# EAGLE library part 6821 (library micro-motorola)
MICROCONTROLLER/MEMORY DEVICE

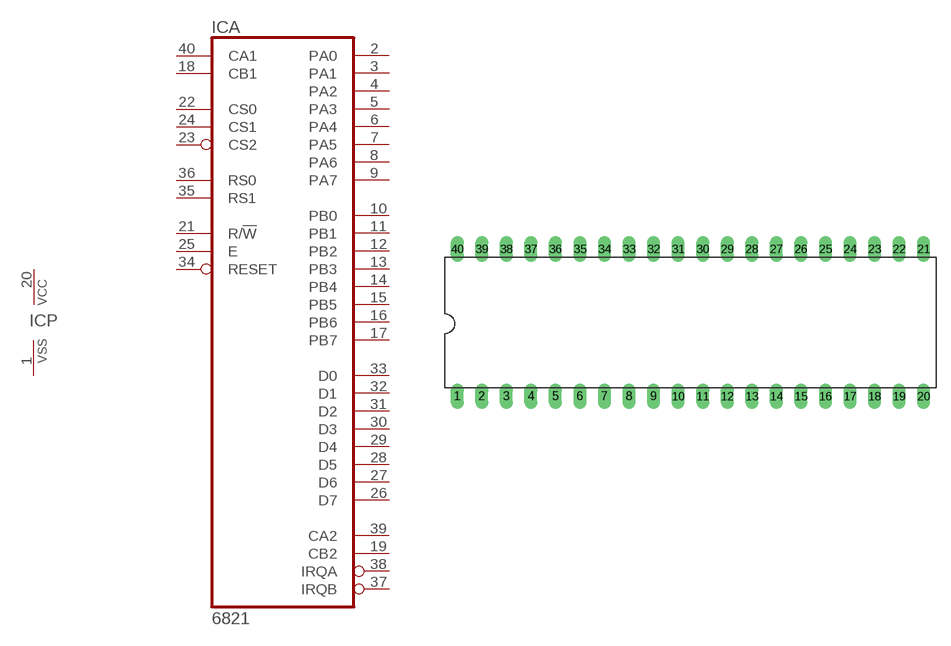
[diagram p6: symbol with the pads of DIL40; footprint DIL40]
Designator prefix IC; gates A=6821 P=PWRVSS

## 6821 (MF: NTE ELECTRONICS; MPN: NTE6821; OC_FARNELL: 1652403; OC_NEWARK: 29C4772)  [DIL40]
1  P:VSS  pwr
2  A:PA0
3  A:PA1
4  A:PA2
5  A:PA3
6  A:PA4
7  A:PA5
8  A:PA6
9  A:PA7
10  A:PB0
11  A:PB1
12  A:PB2
13  A:PB3
14  A:PB4
15  A:PB5
16  A:PB6
17  A:PB7
18  A:CB1  in
19  A:CB2
20  P:VCC  pwr
21  A:R/!W  in
22  A:CS0  in
23  A:CS2  in
24  A:CS1  in
25  A:E  in
26  A:D7
27  A:D6
28  A:D5
29  A:D4
30  A:D3
31  A:D2
32  A:D1
33  A:D0
34  A:RESET  in
35  A:RS1  in
36  A:RS0  in
37  A:IRQB  oc
38  A:IRQA  oc
39  A:CA2
40  A:CA1  in

## Footprint DIL40 (pad centres in mm)
Dual In Line Package
drill 0.813 long: 1 -24.13,-7.62; 2 -21.59,-7.62; 3 -19.05,-7.62; 4 -16.51,-7.62; 5 -13.97,-7.62; 6 -11.43,-7.62; 7 -8.89,-7.62; 8 -6.35,-7.62; 9 -3.81,-7.62; 10 -1.27,-7.62; 11 1.27,-7.62; 12 3.81,-7.62; 13 6.35,-7.62; 14 8.89,-7.62; 15 11.43,-7.62; 16 13.97,-7.62; 17 16.51,-7.62; 18 19.05,-7.62; 19 21.59,-7.62; 20 24.13,-7.62; 21 24.13,7.62; 22 21.59,7.62; 23 19.05,7.62; 24 16.51,7.62; 25 13.97,7.62; 26 11.43,7.62; 27 8.89,7.62; 28 6.35,7.62; 29 3.81,7.62; 30 1.27,7.62; 31 -1.27,7.62; 32 -3.81,7.62; 33 -6.35,7.62; 34 -8.89,7.62; 35 -11.43,7.62; 36 -13.97,7.62; 37 -16.51,7.62; 38 -19.05,7.62; 39 -21.59,7.62; 40 -24.13,7.62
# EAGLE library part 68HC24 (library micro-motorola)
MICROCONTROLLER/MEMORY DEVICE

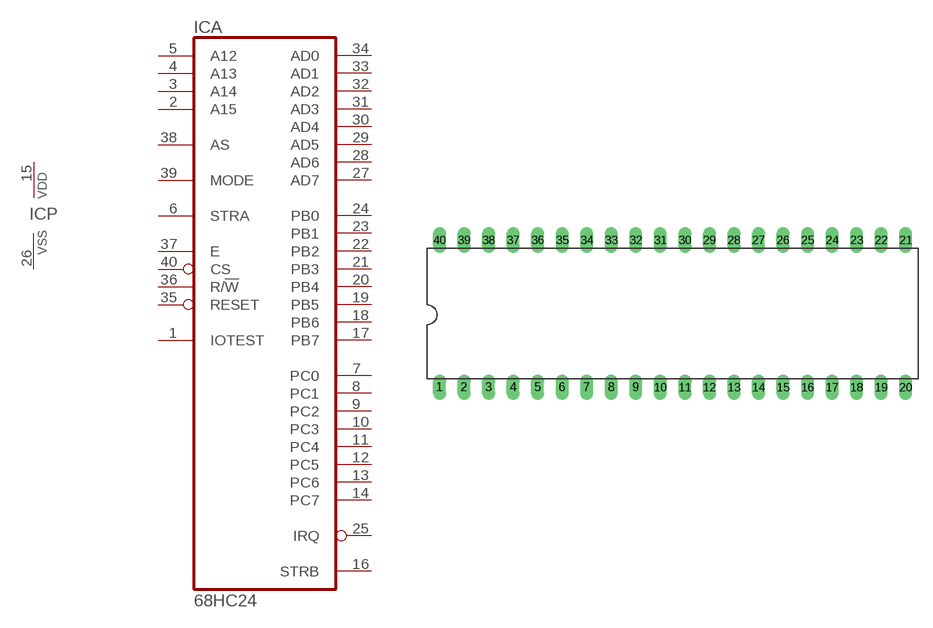
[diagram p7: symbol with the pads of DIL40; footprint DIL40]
Designator prefix IC; gates A=68HC24 P=VSSVDD

## 68HC24 (OC_FARNELL: unknown; OC_NEWARK: unknown)  [DIL40]
1  A:IOTEST  in
2  A:A15  in
3  A:A14  in
4  A:A13  in
5  A:A12  in
6  A:STRA  in
7  A:PC0
8  A:PC1
9  A:PC2
10  A:PC3
11  A:PC4
12  A:PC5
13  A:PC6
14  A:PC7
15  P:VDD  pwr
16  A:STRB  out
17  A:PB7  out
18  A:PB6  out
19  A:PB5  out
20  A:PB4  out
21  A:PB3  out
22  A:PB2  out
23  A:PB1  out
24  A:PB0  out
25  A:IRQ  out
26  P:VSS  pwr
27  A:AD7
28  A:AD6
29  A:AD5
30  A:AD4
31  A:AD3
32  A:AD2
33  A:AD1
34  A:AD0
35  A:RESET  in
36  A:R/!W  in
37  A:E  in
38  A:AS  in
39  A:MODE  in
40  A:CS  in

## Footprint DIL40 (pad centres in mm)
Dual In Line Package
drill 0.813 long: 1 -24.13,-7.62; 2 -21.59,-7.62; 3 -19.05,-7.62; 4 -16.51,-7.62; 5 -13.97,-7.62; 6 -11.43,-7.62; 7 -8.89,-7.62; 8 -6.35,-7.62; 9 -3.81,-7.62; 10 -1.27,-7.62; 11 1.27,-7.62; 12 3.81,-7.62; 13 6.35,-7.62; 14 8.89,-7.62; 15 11.43,-7.62; 16 13.97,-7.62; 17 16.51,-7.62; 18 19.05,-7.62; 19 21.59,-7.62; 20 24.13,-7.62; 21 24.13,7.62; 22 21.59,7.62; 23 19.05,7.62; 24 16.51,7.62; 25 13.97,7.62; 26 11.43,7.62; 27 8.89,7.62; 28 6.35,7.62; 29 3.81,7.62; 30 1.27,7.62; 31 -1.27,7.62; 32 -3.81,7.62; 33 -6.35,7.62; 34 -8.89,7.62; 35 -11.43,7.62; 36 -13.97,7.62; 37 -16.51,7.62; 38 -19.05,7.62; 39 -21.59,7.62; 40 -24.13,7.62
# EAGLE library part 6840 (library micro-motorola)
MICROCONTROLLER/MEMORY DEVICE

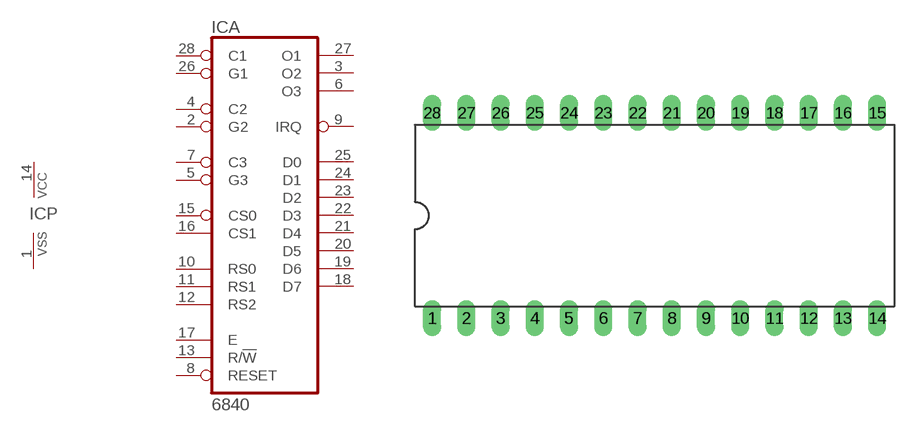
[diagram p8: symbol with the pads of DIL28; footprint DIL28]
Designator prefix IC; gates A=6840 P=PWRVSS

## 6840 (OC_FARNELL: unknown; OC_NEWARK: unknown)  [DIL28]
1  P:VSS  pwr
2  A:G2  in
3  A:O2  out
4  A:C2  in
5  A:G3  in
6  A:O3  out
7  A:C3  in
8  A:RESET  in
9  A:IRQ  oc
10  A:RS0  in
11  A:RS1  in
12  A:RS2  in
13  A:R/!W  in
14  P:VCC  pwr
15  A:CS0  in
16  A:CS1  in
17  A:E  in
18  A:D7
19  A:D6
20  A:D5
21  A:D4
22  A:D3
23  A:D2
24  A:D1
25  A:D0
26  A:G1  in
27  A:O1  out
28  A:C1  in

## Footprint DIL28 (pad centres in mm)
Dual In Line Package
drill 0.813 long: 1 -16.51,-7.62; 2 -13.97,-7.62; 3 -11.43,-7.62; 4 -8.89,-7.62; 5 -6.35,-7.62; 6 -3.81,-7.62; 7 -1.27,-7.62; 8 1.27,-7.62; 9 3.81,-7.62; 10 6.35,-7.62; 11 8.89,-7.62; 12 11.43,-7.62; 13 13.97,-7.62; 14 16.51,-7.62; 15 16.51,7.62; 16 13.97,7.62; 17 11.43,7.62; 18 8.89,7.62; 19 6.35,7.62; 20 3.81,7.62; 21 1.27,7.62; 22 -1.27,7.62; 23 -3.81,7.62; 24 -6.35,7.62; 25 -8.89,7.62; 26 -11.43,7.62; 27 -13.97,7.62; 28 -16.51,7.62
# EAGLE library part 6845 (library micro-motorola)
MICROCONTROLLER/MEMORY DEVICE

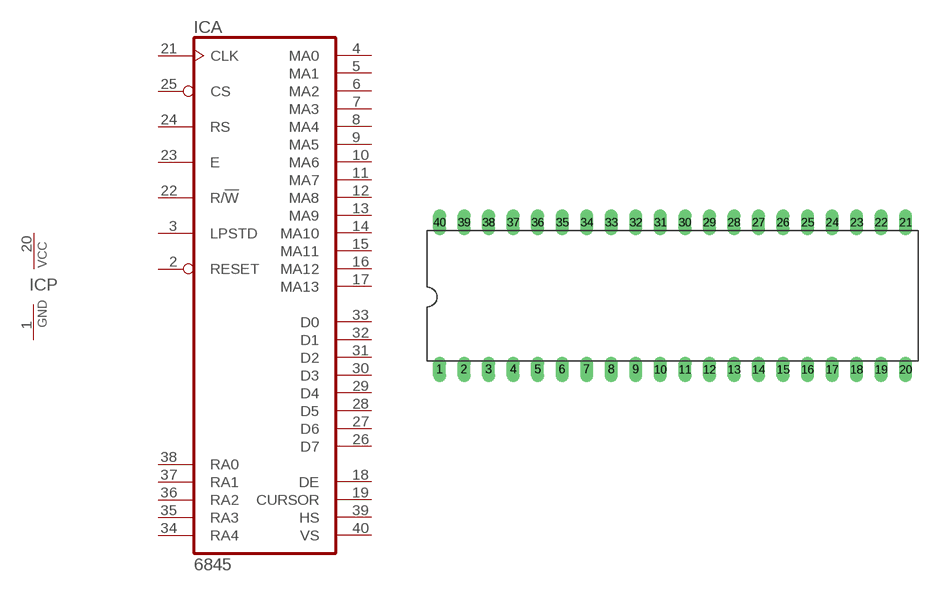
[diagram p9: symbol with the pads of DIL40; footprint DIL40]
Designator prefix IC; gates A=6845 P=PWRN

## 6845 (OC_FARNELL: unknown; OC_NEWARK: unknown)  [DIL40]
1  P:GND  pwr
2  A:RESET  in
3  A:LPSTD  in
4  A:MA0  out
5  A:MA1  out
6  A:MA2  out
7  A:MA3  out
8  A:MA4  out
9  A:MA5  out
10  A:MA6  out
11  A:MA7  out
12  A:MA8  out
13  A:MA9  out
14  A:MA10  out
15  A:MA11  out
16  A:MA12  out
17  A:MA13  out
18  A:DE  out
19  A:CURSOR  out
20  P:VCC  pwr
21  A:CLK  in
22  A:R/!W  in
23  A:E  in
24  A:RS  in
25  A:CS  in
26  A:D7  out
27  A:D6  out
28  A:D5  out
29  A:D4  out
30  A:D3  out
31  A:D2  out
32  A:D1  out
33  A:D0  out
34  A:RA4  out
35  A:RA3  out
36  A:RA2  out
37  A:RA1  out
38  A:RA0  out
39  A:HS  out
40  A:VS  out

## Footprint DIL40 (pad centres in mm)
Dual In Line Package
drill 0.813 long: 1 -24.13,-7.62; 2 -21.59,-7.62; 3 -19.05,-7.62; 4 -16.51,-7.62; 5 -13.97,-7.62; 6 -11.43,-7.62; 7 -8.89,-7.62; 8 -6.35,-7.62; 9 -3.81,-7.62; 10 -1.27,-7.62; 11 1.27,-7.62; 12 3.81,-7.62; 13 6.35,-7.62; 14 8.89,-7.62; 15 11.43,-7.62; 16 13.97,-7.62; 17 16.51,-7.62; 18 19.05,-7.62; 19 21.59,-7.62; 20 24.13,-7.62; 21 24.13,7.62; 22 21.59,7.62; 23 19.05,7.62; 24 16.51,7.62; 25 13.97,7.62; 26 11.43,7.62; 27 8.89,7.62; 28 6.35,7.62; 29 3.81,7.62; 30 1.27,7.62; 31 -1.27,7.62; 32 -3.81,7.62; 33 -6.35,7.62; 34 -8.89,7.62; 35 -11.43,7.62; 36 -13.97,7.62; 37 -16.51,7.62; 38 -19.05,7.62; 39 -21.59,7.62; 40 -24.13,7.62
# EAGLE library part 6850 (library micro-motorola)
MICROCONTROLLER/MEMORY DEVICE

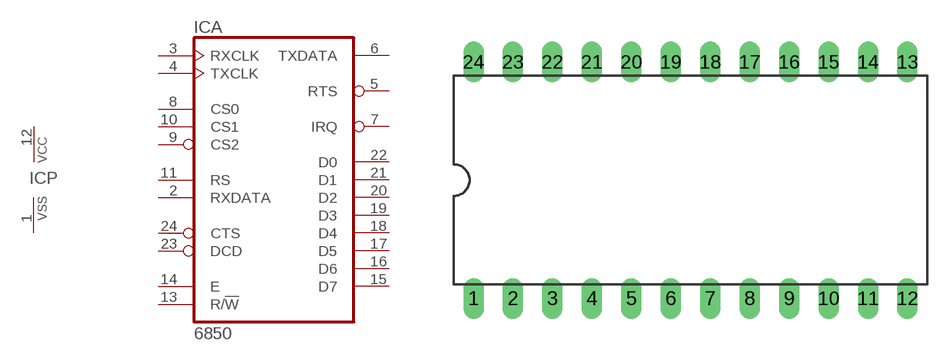
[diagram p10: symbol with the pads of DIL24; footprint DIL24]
Designator prefix IC; gates A=6850 P=PWRVSS

## 6850 (MF: NTE ELECTRONICS; MPN: NTE6850; OC_FARNELL: 4899775; OC_NEWARK: 31C2457)  [DIL24]
1  P:VSS  pwr
2  A:RXDATA  in
3  A:RXCLK  in
4  A:TXCLK  in
5  A:RTS  out
6  A:TXDATA  out
7  A:IRQ  out
8  A:CS0  in
9  A:CS2  in
10  A:CS1  in
11  A:RS  in
12  P:VCC  pwr
13  A:R/!W  in
14  A:E  in
15  A:D7
16  A:D6
17  A:D5
18  A:D4
19  A:D3
20  A:D2
21  A:D1
22  A:D0
23  A:DCD  in
24  A:CTS  in

## Footprint DIL24 (pad centres in mm)
Dual In Line Package
drill 0.813 long: 1 -13.97,-7.62; 2 -11.43,-7.62; 3 -8.89,-7.62; 4 -6.35,-7.62; 5 -3.81,-7.62; 6 -1.27,-7.62; 7 1.27,-7.62; 8 3.81,-7.62; 9 6.35,-7.62; 10 8.89,-7.62; 11 11.43,-7.62; 12 13.97,-7.62; 13 13.97,7.62; 14 11.43,7.62; 15 8.89,7.62; 16 6.35,7.62; 17 3.81,7.62; 18 1.27,7.62; 19 -1.27,7.62; 20 -3.81,7.62; 21 -6.35,7.62; 22 -8.89,7.62; 23 -11.43,7.62; 24 -13.97,7.62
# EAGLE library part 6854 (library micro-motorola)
MICROCONTROLLER/MEMORY DEVICE

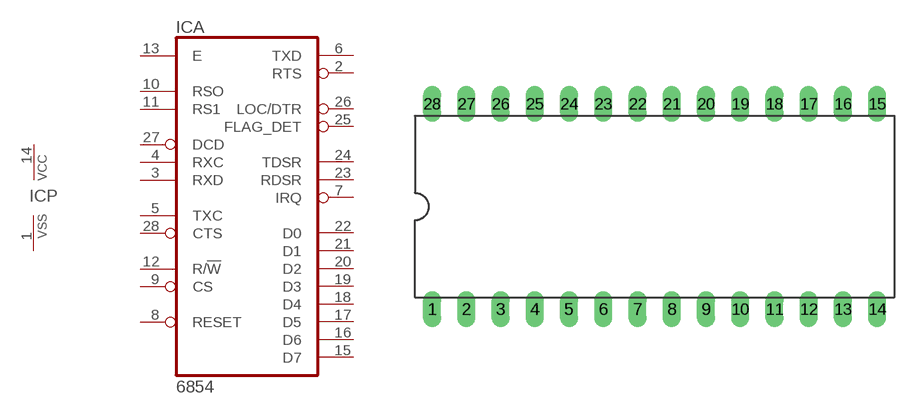
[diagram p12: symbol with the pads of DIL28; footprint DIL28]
Designator prefix IC; gates A=6854 P=PWRVSS

## 6854 (OC_FARNELL: unknown; OC_NEWARK: unknown)  [DIL28]
1  P:VSS  pwr
2  A:RTS  out
3  A:RXD  in
4  A:RXC  in
5  A:TXC  in
6  A:TXD  out
7  A:IRQ  out
8  A:RESET  in
9  A:CS  in
10  A:RSO  in
11  A:RS1  in
12  A:R/!W  in
13  A:E  in
14  P:VCC  pwr
15  A:D7
16  A:D6
17  A:D5
18  A:D4
19  A:D3
20  A:D2
21  A:D1
22  A:D0
23  A:RDSR  out
24  A:TDSR  out
25  A:FLAG_DET  out
26  A:LOC/DTR  out
27  A:DCD  in
28  A:CTS  in

## Footprint DIL28 (pad centres in mm)
Dual In Line Package
drill 0.813 long: 1 -16.51,-7.62; 2 -13.97,-7.62; 3 -11.43,-7.62; 4 -8.89,-7.62; 5 -6.35,-7.62; 6 -3.81,-7.62; 7 -1.27,-7.62; 8 1.27,-7.62; 9 3.81,-7.62; 10 6.35,-7.62; 11 8.89,-7.62; 12 11.43,-7.62; 13 13.97,-7.62; 14 16.51,-7.62; 15 16.51,7.62; 16 13.97,7.62; 17 11.43,7.62; 18 8.89,7.62; 19 6.35,7.62; 20 3.81,7.62; 21 1.27,7.62; 22 -1.27,7.62; 23 -3.81,7.62; 24 -6.35,7.62; 25 -8.89,7.62; 26 -11.43,7.62; 27 -13.97,7.62; 28 -16.51,7.62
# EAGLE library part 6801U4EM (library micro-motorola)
MICROCONTROLLER/MEMORY DEVICE

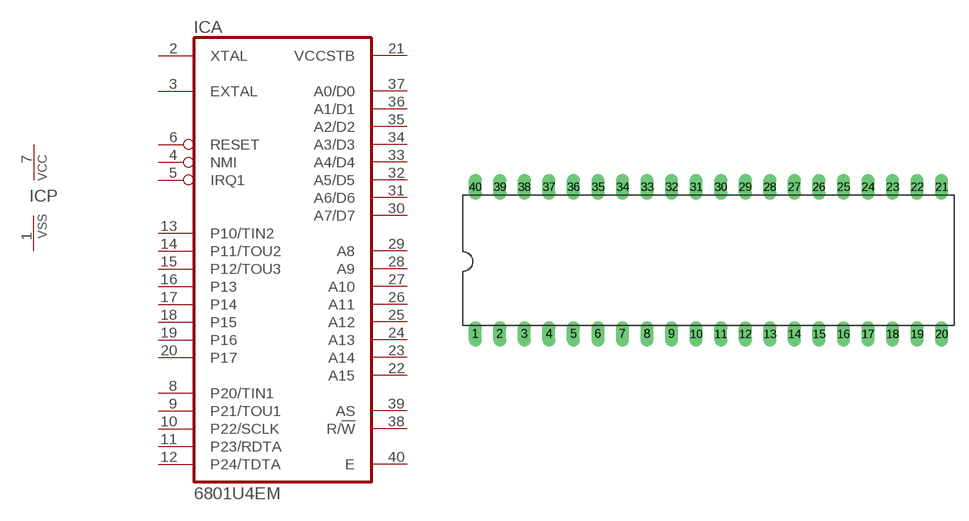
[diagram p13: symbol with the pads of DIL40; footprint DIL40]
Designator prefix IC; gates A=6801U4EM P=PWRVSS

## 6801U4EM (OC_FARNELL: unknown; OC_NEWARK: unknown)  [DIL40]
1  P:VSS  pwr
2  A:XTAL  in
3  A:EXTAL  in
4  A:NMI  in
5  A:IRQ1  in
6  A:RESET  in
7  P:VCC  pwr
8  A:P20/TIN1
9  A:P21/TOU1
10  A:P22/SCLK
11  A:P23/RDTA
12  A:P24/TDTA
13  A:P10/TIN2
14  A:P11/TOU2
15  A:P12/TOU3
16  A:P13
17  A:P14
18  A:P15
19  A:P16
20  A:P17
21  A:VCCSTB  in
22  A:A15
23  A:A14
24  A:A13
25  A:A12
26  A:A11
27  A:A10
28  A:A9
29  A:A8
30  A:A7/D7
31  A:A6/D6
32  A:A5/D5
33  A:A4/D4
34  A:A3/D3
35  A:A2/D2
36  A:A1/D1
37  A:A0/D0
38  A:R/!W  out
39  A:AS
40  A:E  out

## Footprint DIL40 (pad centres in mm)
Dual In Line Package
drill 0.813 long: 1 -24.13,-7.62; 2 -21.59,-7.62; 3 -19.05,-7.62; 4 -16.51,-7.62; 5 -13.97,-7.62; 6 -11.43,-7.62; 7 -8.89,-7.62; 8 -6.35,-7.62; 9 -3.81,-7.62; 10 -1.27,-7.62; 11 1.27,-7.62; 12 3.81,-7.62; 13 6.35,-7.62; 14 8.89,-7.62; 15 11.43,-7.62; 16 13.97,-7.62; 17 16.51,-7.62; 18 19.05,-7.62; 19 21.59,-7.62; 20 24.13,-7.62; 21 24.13,7.62; 22 21.59,7.62; 23 19.05,7.62; 24 16.51,7.62; 25 13.97,7.62; 26 11.43,7.62; 27 8.89,7.62; 28 6.35,7.62; 29 3.81,7.62; 30 1.27,7.62; 31 -1.27,7.62; 32 -3.81,7.62; 33 -6.35,7.62; 34 -8.89,7.62; 35 -11.43,7.62; 36 -13.97,7.62; 37 -16.51,7.62; 38 -19.05,7.62; 39 -21.59,7.62; 40 -24.13,7.62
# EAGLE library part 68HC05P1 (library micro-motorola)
MICROCONTROLLER/MEMORY DEVICE

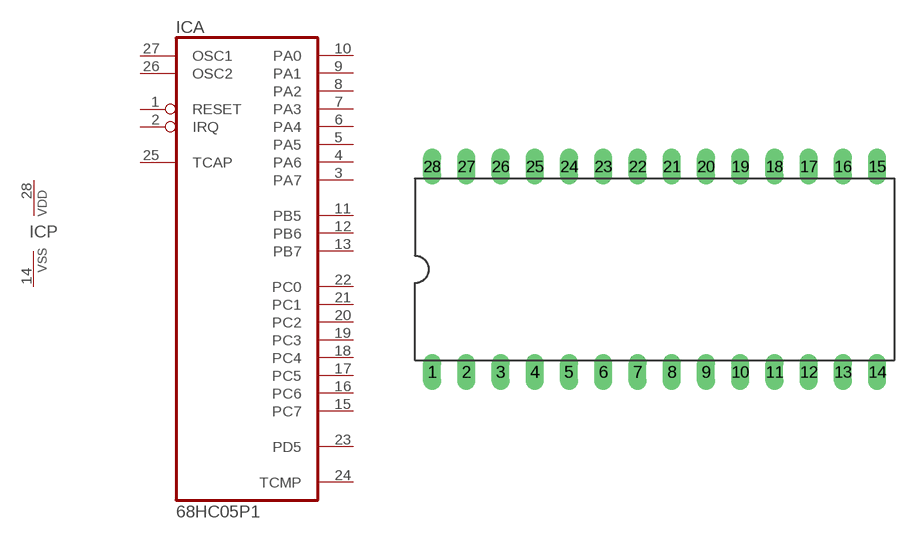
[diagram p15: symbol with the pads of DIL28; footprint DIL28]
Designator prefix IC; gates A=68HC05P1 P=VSSVDD

## 68HC05P1 (OC_FARNELL: unknown; OC_NEWARK: unknown)  [DIL28]
1  A:RESET  in
2  A:IRQ  in
3  A:PA7
4  A:PA6
5  A:PA5
6  A:PA4
7  A:PA3
8  A:PA2
9  A:PA1
10  A:PA0
11  A:PB5
12  A:PB6
13  A:PB7
14  P:VSS  pwr
15  A:PC7
16  A:PC6
17  A:PC5
18  A:PC4
19  A:PC3
20  A:PC2
21  A:PC1
22  A:PC0
23  A:PD5
24  A:TCMP  out
25  A:TCAP  in
26  A:OSC2  pas
27  A:OSC1  in
28  P:VDD  pwr

## Footprint DIL28 (pad centres in mm)
Dual In Line Package
drill 0.813 long: 1 -16.51,-7.62; 2 -13.97,-7.62; 3 -11.43,-7.62; 4 -8.89,-7.62; 5 -6.35,-7.62; 6 -3.81,-7.62; 7 -1.27,-7.62; 8 1.27,-7.62; 9 3.81,-7.62; 10 6.35,-7.62; 11 8.89,-7.62; 12 11.43,-7.62; 13 13.97,-7.62; 14 16.51,-7.62; 15 16.51,7.62; 16 13.97,7.62; 17 11.43,7.62; 18 8.89,7.62; 19 6.35,7.62; 20 3.81,7.62; 21 1.27,7.62; 22 -1.27,7.62; 23 -3.81,7.62; 24 -6.35,7.62; 25 -8.89,7.62; 26 -11.43,7.62; 27 -13.97,7.62; 28 -16.51,7.62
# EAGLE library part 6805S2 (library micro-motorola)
MICROCONTROLLER/MEMORY DEVICE

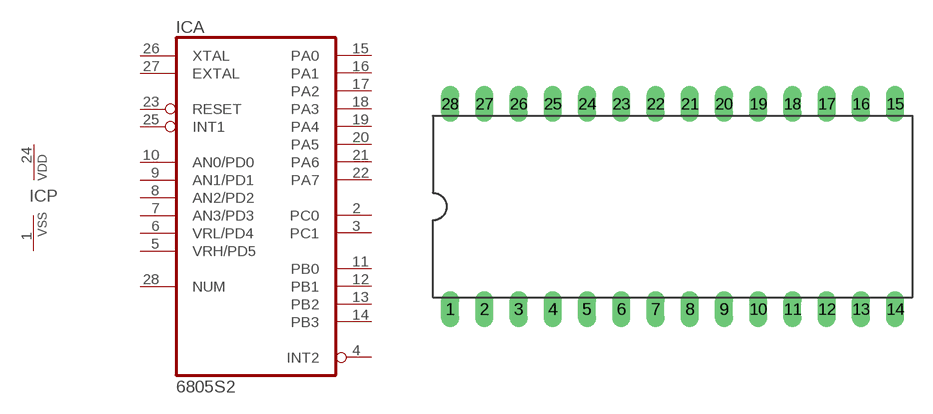
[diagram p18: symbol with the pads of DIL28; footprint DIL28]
Designator prefix IC; gates A=6805S2 P=VSSVDD

## 6805S2 (OC_FARNELL: unknown; OC_NEWARK: unknown)  [DIL28]
1  P:VSS  pwr
2  A:PC0
3  A:PC1
4  A:INT2
5  A:VRH/PD5  in
6  A:VRL/PD4  in
7  A:AN3/PD3  in
8  A:AN2/PD2  in
9  A:AN1/PD1  in
10  A:AN0/PD0  in
11  A:PB0
12  A:PB1
13  A:PB2
14  A:PB3
15  A:PA0
16  A:PA1
17  A:PA2
18  A:PA3
19  A:PA4
20  A:PA5
21  A:PA6
22  A:PA7
23  A:RESET  in
24  P:VDD  pwr
25  A:INT1  in
26  A:XTAL  in
27  A:EXTAL  in
28  A:NUM  in

## Footprint DIL28 (pad centres in mm)
Dual In Line Package
drill 0.813 long: 1 -16.51,-7.62; 2 -13.97,-7.62; 3 -11.43,-7.62; 4 -8.89,-7.62; 5 -6.35,-7.62; 6 -3.81,-7.62; 7 -1.27,-7.62; 8 1.27,-7.62; 9 3.81,-7.62; 10 6.35,-7.62; 11 8.89,-7.62; 12 11.43,-7.62; 13 13.97,-7.62; 14 16.51,-7.62; 15 16.51,7.62; 16 13.97,7.62; 17 11.43,7.62; 18 8.89,7.62; 19 6.35,7.62; 20 3.81,7.62; 21 1.27,7.62; 22 -1.27,7.62; 23 -3.81,7.62; 24 -6.35,7.62; 25 -8.89,7.62; 26 -11.43,7.62; 27 -13.97,7.62; 28 -16.51,7.62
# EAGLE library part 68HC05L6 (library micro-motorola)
MICROCONTROLLER/MEMORY DEVICE

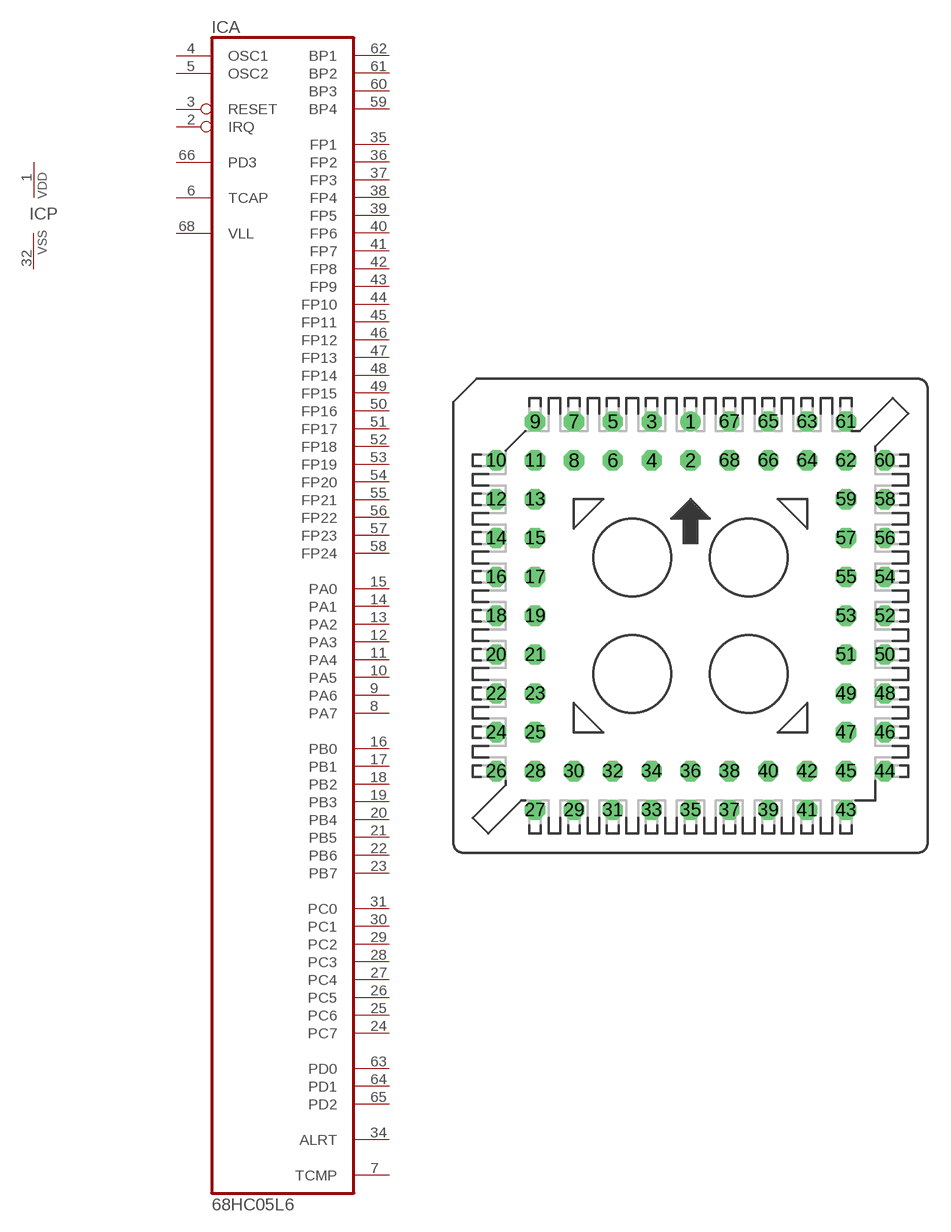
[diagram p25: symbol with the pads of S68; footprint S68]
Designator prefix IC; gates A=68HC05L6 P=VSSVDD

## 68HC05L6 (OC_FARNELL: unknown; OC_NEWARK: unknown)  [S68]
1  P:VDD  pwr
2  A:IRQ  in
3  A:RESET  in
4  A:OSC1  in
5  A:OSC2  pas
6  A:TCAP  in
7  A:TCMP  out
8  A:PA7
9  A:PA6
10  A:PA5
11  A:PA4
12  A:PA3
13  A:PA2
14  A:PA1
15  A:PA0
16  A:PB0
17  A:PB1
18  A:PB2
19  A:PB3
20  A:PB4
21  A:PB5
22  A:PB6
23  A:PB7
24  A:PC7
25  A:PC6
26  A:PC5
27  A:PC4
28  A:PC3
29  A:PC2
30  A:PC1
31  A:PC0
32  P:VSS  pwr
34  A:ALRT  out
35  A:FP1  out
36  A:FP2  out
37  A:FP3  out
38  A:FP4  out
39  A:FP5  out
40  A:FP6  out
41  A:FP7  out
42  A:FP8  out
43  A:FP9  out
44  A:FP10  out
45  A:FP11  out
46  A:FP12  out
47  A:FP13  out
48  A:FP14  out
49  A:FP15  out
50  A:FP16  out
51  A:FP17  out
52  A:FP18  out
53  A:FP19  out
54  A:FP20  out
55  A:FP21  out
56  A:FP22  out
57  A:FP23  out
58  A:FP24  out
59  A:BP4  out
60  A:BP3  out
61  A:BP2  out
62  A:BP1  out
63  A:PD0
64  A:PD1
65  A:PD2
66  A:PD3  in
68  A:VLL  in

## Footprint S68 (pad centres in mm)
PLCC SOCKET
drill 0.813 round: 1 0,12.7
drill 0.813 octagon: 2 0,10.16; 3 -2.54,12.7; 4 -2.54,10.16; 5 -5.08,12.7; 6 -5.08,10.16; 7 -7.62,12.7; 8 -7.62,10.16; 9 -10.16,12.7; 10 -12.7,10.16; 11 -10.16,10.16; 12 -12.7,7.62; 13 -10.16,7.62; 14 -12.7,5.08; 15 -10.16,5.08; 16 -12.7,2.54; 17 -10.16,2.54; 18 -12.7,0; 19 -10.16,0; 20 -12.7,-2.54; 21 -10.16,-2.54; 22 -12.7,-5.08; 23 -10.16,-5.08; 24 -12.7,-7.62; 25 -10.16,-7.62; 26 -12.7,-10.16; 27 -10.16,-12.7; 28 -10.16,-10.16; 29 -7.62,-12.7; 30 -7.62,-10.16; 31 -5.08,-12.7; 32 -5.08,-10.16; 33 -2.54,-12.7; 34 -2.54,-10.16; 35 0,-12.7; 36 0,-10.16; 37 2.54,-12.7; 38 2.54,-10.16; 39 5.08,-12.7; 40 5.08,-10.16; 41 7.62,-12.7; 42 7.62,-10.16; 43 10.16,-12.7; 44 12.7,-10.16; 45 10.16,-10.16; 46 12.7,-7.62; 47 10.16,-7.62; 48 12.7,-5.08; 49 10.16,-5.08; 50 12.7,-2.54; 51 10.16,-2.54; 52 12.7,0; 53 10.16,0; 54 12.7,2.54; 55 10.16,2.54; 56 12.7,5.08; 57 10.16,5.08; 58 12.7,7.62; 59 10.16,7.62; 60 12.7,10.16; 61 10.16,12.7; 62 10.16,10.16; 63 7.62,12.7; 64 7.62,10.16; 65 5.08,12.7; 66 5.08,10.16; 67 2.54,12.7; 68 2.54,10.16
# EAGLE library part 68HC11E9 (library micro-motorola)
MICROCONTROLLER/MEMORY DEVICE

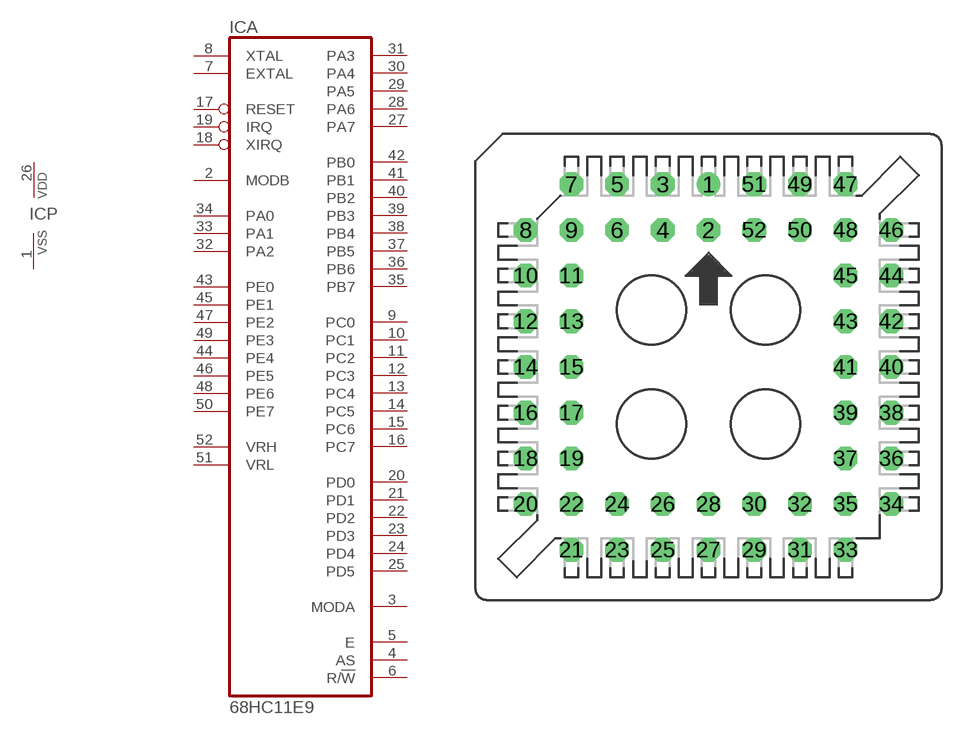
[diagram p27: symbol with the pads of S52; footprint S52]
Designator prefix IC; gates A=68HC11E9 P=VSSVDD

## 68HC11E9 (MF: MOTOROLA; MPN: MC68HC11E9BCFNE2; OC_FARNELL: 1607932; OC_NEWARK: 68K9829)  [S52]
1  P:VSS  pwr
2  A:MODB  in
3  A:MODA
4  A:AS
5  A:E  out
6  A:R/!W
7  A:EXTAL
8  A:XTAL  out
9  A:PC0
10  A:PC1
11  A:PC2
12  A:PC3
13  A:PC4
14  A:PC5
15  A:PC6
16  A:PC7
17  A:RESET
18  A:XIRQ  in
19  A:IRQ  in
20  A:PD0
21  A:PD1
22  A:PD2
23  A:PD3
24  A:PD4
25  A:PD5
26  P:VDD  pwr
27  A:PA7
28  A:PA6  out
29  A:PA5  out
30  A:PA4  out
31  A:PA3
32  A:PA2  in
33  A:PA1  in
34  A:PA0  in
35  A:PB7  out
36  A:PB6  out
37  A:PB5  out
38  A:PB4  out
39  A:PB3  out
40  A:PB2  out
41  A:PB1  out
42  A:PB0  out
43  A:PE0  in
44  A:PE4  in
45  A:PE1  in
46  A:PE5  in
47  A:PE2  in
48  A:PE6  in
49  A:PE3  in
50  A:PE7  in
51  A:VRL  in
52  A:VRH  in

## Footprint S52 (pad centres in mm)
PLCC SOCKET
drill 0.813 round: 1 0,10.16
drill 0.813 octagon: 2 0,7.62; 3 -2.54,10.16; 4 -2.54,7.62; 5 -5.08,10.16; 6 -5.08,7.62; 7 -7.62,10.16; 8 -10.16,7.62; 9 -7.62,7.62; 10 -10.16,5.08; 11 -7.62,5.08; 12 -10.16,2.54; 13 -7.62,2.54; 14 -10.16,0; 15 -7.62,0; 16 -10.16,-2.54; 17 -7.62,-2.54; 18 -10.16,-5.08; 19 -7.62,-5.08; 20 -10.16,-7.62; 21 -7.62,-10.16; 22 -7.62,-7.62; 23 -5.08,-10.16; 24 -5.08,-7.62; 25 -2.54,-10.16; 26 -2.54,-7.62; 27 0,-10.16; 28 0,-7.62; 29 2.54,-10.16; 30 2.54,-7.62; 31 5.08,-10.16; 32 5.08,-7.62; 33 7.62,-10.16; 34 10.16,-7.62; 35 7.62,-7.62; 36 10.16,-5.08; 37 7.62,-5.08; 38 10.16,-2.54; 39 7.62,-2.54; 40 10.16,0; 41 7.62,0; 42 10.16,2.54; 43 7.62,2.54; 44 10.16,5.08; 45 7.62,5.08; 46 10.16,7.62; 47 7.62,10.16; 48 7.62,7.62; 49 5.08,10.16; 50 5.08,7.62; 51 2.54,10.16; 52 2.54,7.62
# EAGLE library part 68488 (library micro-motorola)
MICROCONTROLLER/MEMORY DEVICE

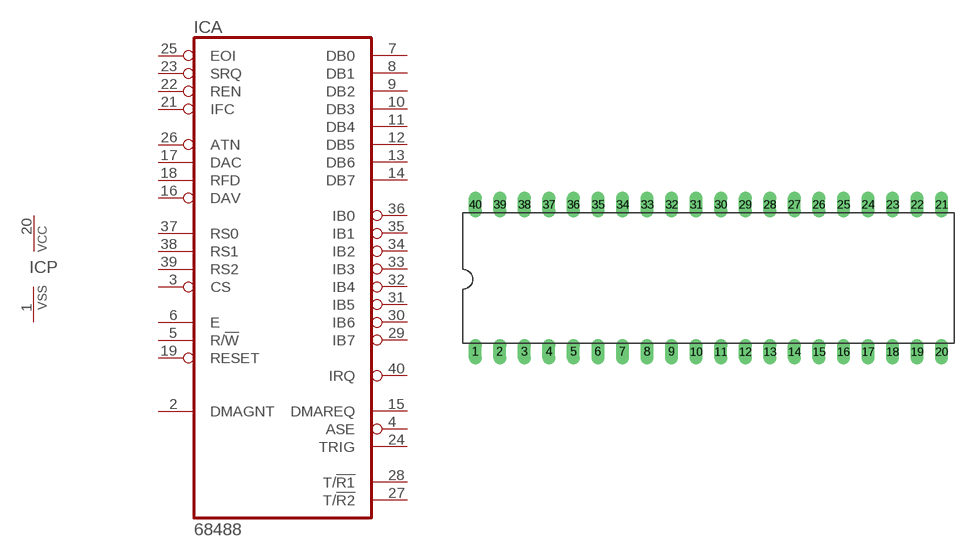
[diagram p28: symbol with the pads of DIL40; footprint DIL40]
Designator prefix IC; gates A=68488 P=PWRVSS

## 68488 (OC_FARNELL: unknown; OC_NEWARK: unknown)  [DIL40]
1  P:VSS  pwr
2  A:DMAGNT  in
3  A:CS  in
4  A:ASE  out
5  A:R/!W  in
6  A:E  in
7  A:DB0
8  A:DB1
9  A:DB2
10  A:DB3
11  A:DB4
12  A:DB5
13  A:DB6
14  A:DB7
15  A:DMAREQ  out
16  A:DAV
17  A:DAC
18  A:RFD
19  A:RESET  in
20  P:VCC  pwr
21  A:IFC  in
22  A:REN  in
23  A:SRQ
24  A:TRIG  out
25  A:EOI
26  A:ATN  in
27  A:T/!R2
28  A:T/!R1
29  A:IB7
30  A:IB6
31  A:IB5
32  A:IB4
33  A:IB3
34  A:IB2
35  A:IB1
36  A:IB0
37  A:RS0  in
38  A:RS1  in
39  A:RS2  in
40  A:IRQ  out

## Footprint DIL40 (pad centres in mm)
Dual In Line Package
drill 0.813 long: 1 -24.13,-7.62; 2 -21.59,-7.62; 3 -19.05,-7.62; 4 -16.51,-7.62; 5 -13.97,-7.62; 6 -11.43,-7.62; 7 -8.89,-7.62; 8 -6.35,-7.62; 9 -3.81,-7.62; 10 -1.27,-7.62; 11 1.27,-7.62; 12 3.81,-7.62; 13 6.35,-7.62; 14 8.89,-7.62; 15 11.43,-7.62; 16 13.97,-7.62; 17 16.51,-7.62; 18 19.05,-7.62; 19 21.59,-7.62; 20 24.13,-7.62; 21 24.13,7.62; 22 21.59,7.62; 23 19.05,7.62; 24 16.51,7.62; 25 13.97,7.62; 26 11.43,7.62; 27 8.89,7.62; 28 6.35,7.62; 29 3.81,7.62; 30 1.27,7.62; 31 -1.27,7.62; 32 -3.81,7.62; 33 -6.35,7.62; 34 -8.89,7.62; 35 -11.43,7.62; 36 -13.97,7.62; 37 -16.51,7.62; 38 -19.05,7.62; 39 -21.59,7.62; 40 -24.13,7.62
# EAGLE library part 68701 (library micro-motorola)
MICROCONTROLLER/MEMORY DEVICE

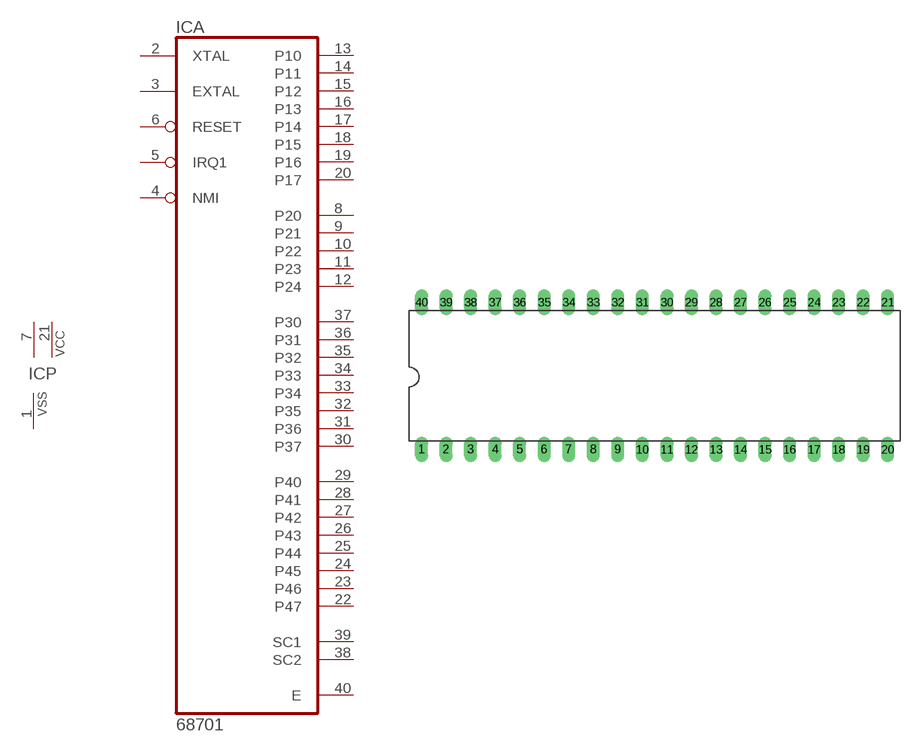
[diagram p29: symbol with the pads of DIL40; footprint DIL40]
Designator prefix IC; gates A=68701 P=2PWRVSS

## 68701 (OC_FARNELL: unknown; OC_NEWARK: unknown)  [DIL40]
1  P:VSS  pwr
2  A:XTAL  in
3  A:EXTAL  in
4  A:NMI  in
5  A:IRQ1  in
6  A:RESET  in
7  P:VCC  pwr
8  A:P20
9  A:P21
10  A:P22
11  A:P23
12  A:P24
13  A:P10
14  A:P11
15  A:P12
16  A:P13
17  A:P14
18  A:P15
19  A:P16
20  A:P17
21  P:VCC  pwr
22  A:P47
23  A:P46
24  A:P45
25  A:P44
26  A:P43
27  A:P42
28  A:P41
29  A:P40
30  A:P37
31  A:P36
32  A:P35
33  A:P34
34  A:P33
35  A:P32
36  A:P31
37  A:P30
38  A:SC2  out
39  A:SC1
40  A:E  out

## Footprint DIL40 (pad centres in mm)
Dual In Line Package
drill 0.813 long: 1 -24.13,-7.62; 2 -21.59,-7.62; 3 -19.05,-7.62; 4 -16.51,-7.62; 5 -13.97,-7.62; 6 -11.43,-7.62; 7 -8.89,-7.62; 8 -6.35,-7.62; 9 -3.81,-7.62; 10 -1.27,-7.62; 11 1.27,-7.62; 12 3.81,-7.62; 13 6.35,-7.62; 14 8.89,-7.62; 15 11.43,-7.62; 16 13.97,-7.62; 17 16.51,-7.62; 18 19.05,-7.62; 19 21.59,-7.62; 20 24.13,-7.62; 21 24.13,7.62; 22 21.59,7.62; 23 19.05,7.62; 24 16.51,7.62; 25 13.97,7.62; 26 11.43,7.62; 27 8.89,7.62; 28 6.35,7.62; 29 3.81,7.62; 30 1.27,7.62; 31 -1.27,7.62; 32 -3.81,7.62; 33 -6.35,7.62; 34 -8.89,7.62; 35 -11.43,7.62; 36 -13.97,7.62; 37 -16.51,7.62; 38 -19.05,7.62; 39 -21.59,7.62; 40 -24.13,7.62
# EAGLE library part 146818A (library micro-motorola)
MICROCONTROLLER/MEMORY DEVICE

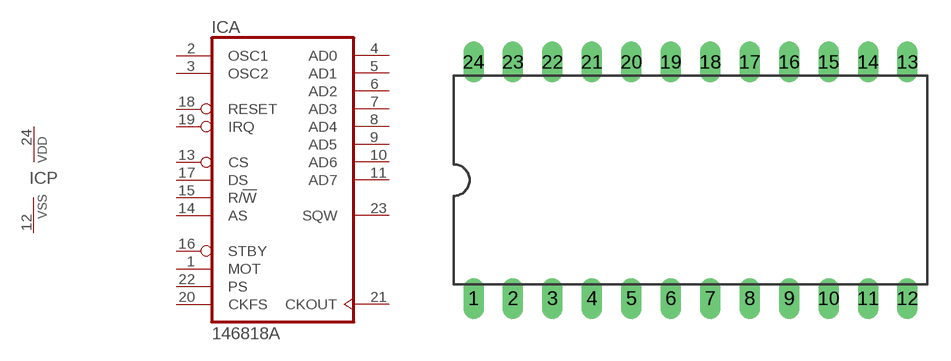
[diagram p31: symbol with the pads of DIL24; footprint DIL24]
Designator prefix IC; gates A=146818A P=VSSVDD

## 146818A (OC_FARNELL: unknown; OC_NEWARK: unknown)  [DIL24]
1  A:MOT  in
2  A:OSC1  in
3  A:OSC2  pas
4  A:AD0
5  A:AD1
6  A:AD2
7  A:AD3
8  A:AD4
9  A:AD5
10  A:AD6
11  A:AD7
12  P:VSS  pwr
13  A:CS  in
14  A:AS  in
15  A:R/!W  in
16  A:STBY  in
17  A:DS  in
18  A:RESET  in
19  A:IRQ  out
20  A:CKFS  in
21  A:CKOUT  out
22  A:PS  in
23  A:SQW  out
24  P:VDD  pwr

## Footprint DIL24 (pad centres in mm)
Dual In Line Package
drill 0.813 long: 1 -13.97,-7.62; 2 -11.43,-7.62; 3 -8.89,-7.62; 4 -6.35,-7.62; 5 -3.81,-7.62; 6 -1.27,-7.62; 7 1.27,-7.62; 8 3.81,-7.62; 9 6.35,-7.62; 10 8.89,-7.62; 11 11.43,-7.62; 12 13.97,-7.62; 13 13.97,7.62; 14 11.43,7.62; 15 8.89,7.62; 16 6.35,7.62; 17 3.81,7.62; 18 1.27,7.62; 19 -1.27,7.62; 20 -3.81,7.62; 21 -6.35,7.62; 22 -8.89,7.62; 23 -11.43,7.62; 24 -13.97,7.62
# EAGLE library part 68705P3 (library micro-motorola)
MICROCONTROLLER/MEMORY DEVICE

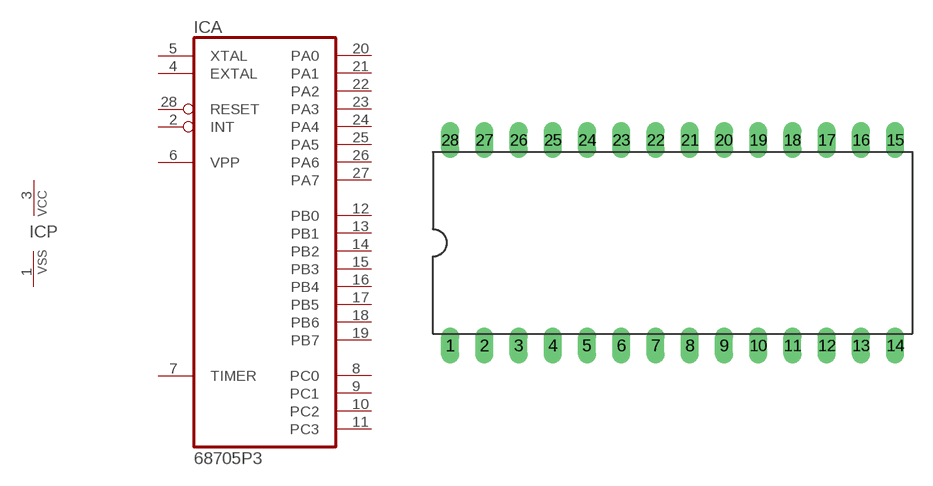
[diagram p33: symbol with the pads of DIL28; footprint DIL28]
Designator prefix IC; gates A=68705P3 P=PWRVSS

## 68705P3 (OC_FARNELL: unknown; OC_NEWARK: unknown)  [DIL28]
1  P:VSS  pwr
2  A:INT  in
3  P:VCC  pwr
4  A:EXTAL  in
5  A:XTAL  in
6  A:VPP  in
7  A:TIMER
8  A:PC0
9  A:PC1
10  A:PC2
11  A:PC3
12  A:PB0
13  A:PB1
14  A:PB2
15  A:PB3
16  A:PB4
17  A:PB5
18  A:PB6
19  A:PB7
20  A:PA0
21  A:PA1
22  A:PA2
23  A:PA3
24  A:PA4
25  A:PA5
26  A:PA6
27  A:PA7
28  A:RESET  in

## Footprint DIL28 (pad centres in mm)
Dual In Line Package
drill 0.813 long: 1 -16.51,-7.62; 2 -13.97,-7.62; 3 -11.43,-7.62; 4 -8.89,-7.62; 5 -6.35,-7.62; 6 -3.81,-7.62; 7 -1.27,-7.62; 8 1.27,-7.62; 9 3.81,-7.62; 10 6.35,-7.62; 11 8.89,-7.62; 12 11.43,-7.62; 13 13.97,-7.62; 14 16.51,-7.62; 15 16.51,7.62; 16 13.97,7.62; 17 11.43,7.62; 18 8.89,7.62; 19 6.35,7.62; 20 3.81,7.62; 21 1.27,7.62; 22 -1.27,7.62; 23 -3.81,7.62; 24 -6.35,7.62; 25 -8.89,7.62; 26 -11.43,7.62; 27 -13.97,7.62; 28 -16.51,7.62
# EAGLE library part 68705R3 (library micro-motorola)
MICROCONTROLLER/MEMORY DEVICE

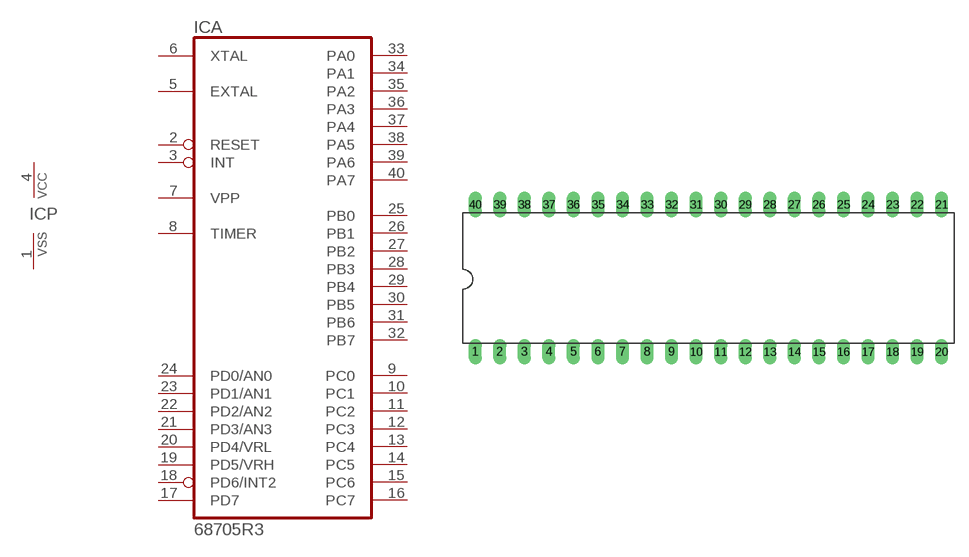
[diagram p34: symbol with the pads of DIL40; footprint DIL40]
Designator prefix IC; gates A=68705R3 P=PWRVSS

## 68705R3 (OC_FARNELL: unknown; OC_NEWARK: unknown)  [DIL40]
1  P:VSS  pwr
2  A:RESET  in
3  A:INT  in
4  P:VCC  pwr
5  A:EXTAL  in
6  A:XTAL  in
7  A:VPP  in
8  A:TIMER  in
9  A:PC0
10  A:PC1
11  A:PC2
12  A:PC3
13  A:PC4
14  A:PC5
15  A:PC6
16  A:PC7
17  A:PD7  in
18  A:PD6/INT2  in
19  A:PD5/VRH  in
20  A:PD4/VRL  in
21  A:PD3/AN3  in
22  A:PD2/AN2  in
23  A:PD1/AN1  in
24  A:PD0/AN0  in
25  A:PB0
26  A:PB1
27  A:PB2
28  A:PB3
29  A:PB4
30  A:PB5
31  A:PB6
32  A:PB7
33  A:PA0
34  A:PA1
35  A:PA2
36  A:PA3
37  A:PA4
38  A:PA5
39  A:PA6
40  A:PA7

## Footprint DIL40 (pad centres in mm)
Dual In Line Package
drill 0.813 long: 1 -24.13,-7.62; 2 -21.59,-7.62; 3 -19.05,-7.62; 4 -16.51,-7.62; 5 -13.97,-7.62; 6 -11.43,-7.62; 7 -8.89,-7.62; 8 -6.35,-7.62; 9 -3.81,-7.62; 10 -1.27,-7.62; 11 1.27,-7.62; 12 3.81,-7.62; 13 6.35,-7.62; 14 8.89,-7.62; 15 11.43,-7.62; 16 13.97,-7.62; 17 16.51,-7.62; 18 19.05,-7.62; 19 21.59,-7.62; 20 24.13,-7.62; 21 24.13,7.62; 22 21.59,7.62; 23 19.05,7.62; 24 16.51,7.62; 25 13.97,7.62; 26 11.43,7.62; 27 8.89,7.62; 28 6.35,7.62; 29 3.81,7.62; 30 1.27,7.62; 31 -1.27,7.62; 32 -3.81,7.62; 33 -6.35,7.62; 34 -8.89,7.62; 35 -11.43,7.62; 36 -13.97,7.62; 37 -16.51,7.62; 38 -19.05,7.62; 39 -21.59,7.62; 40 -24.13,7.62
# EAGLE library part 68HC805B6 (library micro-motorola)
MICROCONTROLLER/MEMORY DEVICE

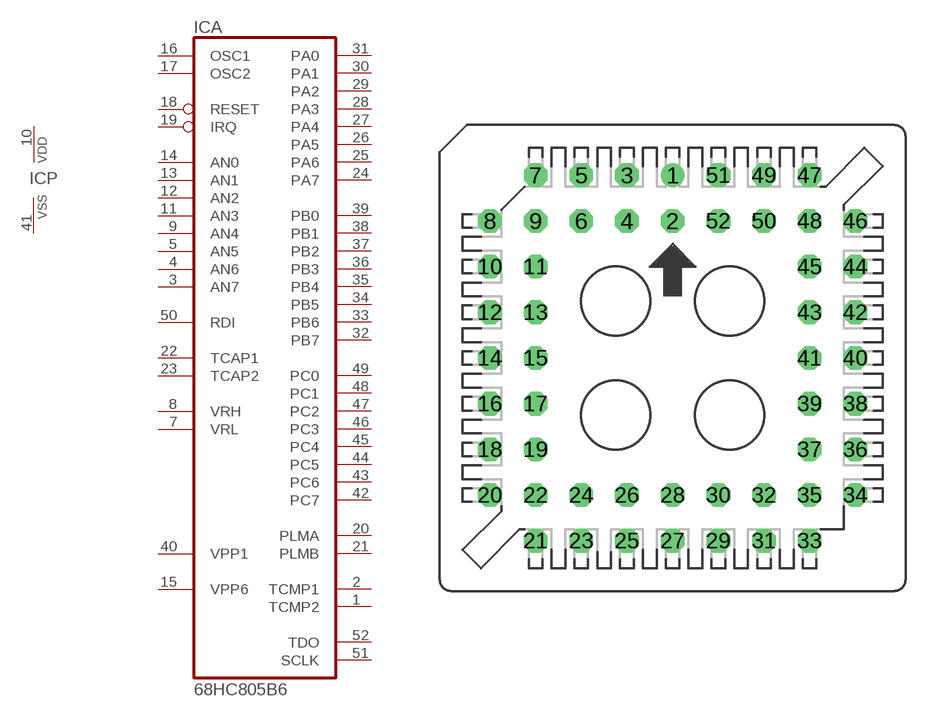
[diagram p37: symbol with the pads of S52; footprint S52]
Designator prefix IC; gates A=68HC05B6 P=VSSVDD

## 68HC805B6 (OC_FARNELL: unknown; OC_NEWARK: unknown)  [S52]
1  A:TCMP2  out
2  A:TCMP1  out
3  A:AN7  in
4  A:AN6  in
5  A:AN5  in
7  A:VRL  in
8  A:VRH  in
9  A:AN4  in
10  P:VDD  pwr
11  A:AN3  in
12  A:AN2  in
13  A:AN1  in
14  A:AN0  in
15  A:VPP6  pwr
16  A:OSC1  in
17  A:OSC2  pas
18  A:RESET
19  A:IRQ  in
20  A:PLMA  out
21  A:PLMB  out
22  A:TCAP1  in
23  A:TCAP2  in
24  A:PA7
25  A:PA6
26  A:PA5
27  A:PA4
28  A:PA3
29  A:PA2
30  A:PA1
31  A:PA0
32  A:PB7
33  A:PB6
34  A:PB5
35  A:PB4
36  A:PB3
37  A:PB2
38  A:PB1
39  A:PB0
40  A:VPP1  pwr
41  P:VSS  pwr
42  A:PC7
43  A:PC6
44  A:PC5
45  A:PC4
46  A:PC3
47  A:PC2
48  A:PC1
49  A:PC0
50  A:RDI  in
51  A:SCLK  out
52  A:TDO  out

## Footprint S52 (pad centres in mm)
PLCC SOCKET
drill 0.813 round: 1 0,10.16
drill 0.813 octagon: 2 0,7.62; 3 -2.54,10.16; 4 -2.54,7.62; 5 -5.08,10.16; 6 -5.08,7.62; 7 -7.62,10.16; 8 -10.16,7.62; 9 -7.62,7.62; 10 -10.16,5.08; 11 -7.62,5.08; 12 -10.16,2.54; 13 -7.62,2.54; 14 -10.16,0; 15 -7.62,0; 16 -10.16,-2.54; 17 -7.62,-2.54; 18 -10.16,-5.08; 19 -7.62,-5.08; 20 -10.16,-7.62; 21 -7.62,-10.16; 22 -7.62,-7.62; 23 -5.08,-10.16; 24 -5.08,-7.62; 25 -2.54,-10.16; 26 -2.54,-7.62; 27 0,-10.16; 28 0,-7.62; 29 2.54,-10.16; 30 2.54,-7.62; 31 5.08,-10.16; 32 5.08,-7.62; 33 7.62,-10.16; 34 10.16,-7.62; 35 7.62,-7.62; 36 10.16,-5.08; 37 7.62,-5.08; 38 10.16,-2.54; 39 7.62,-2.54; 40 10.16,0; 41 7.62,0; 42 10.16,2.54; 43 7.62,2.54; 44 10.16,5.08; 45 7.62,5.08; 46 10.16,7.62; 47 7.62,10.16; 48 7.62,7.62; 49 5.08,10.16; 50 5.08,7.62; 51 2.54,10.16; 52 2.54,7.62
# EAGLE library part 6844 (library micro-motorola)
MICROCONTROLLER/MEMORY DEVICE

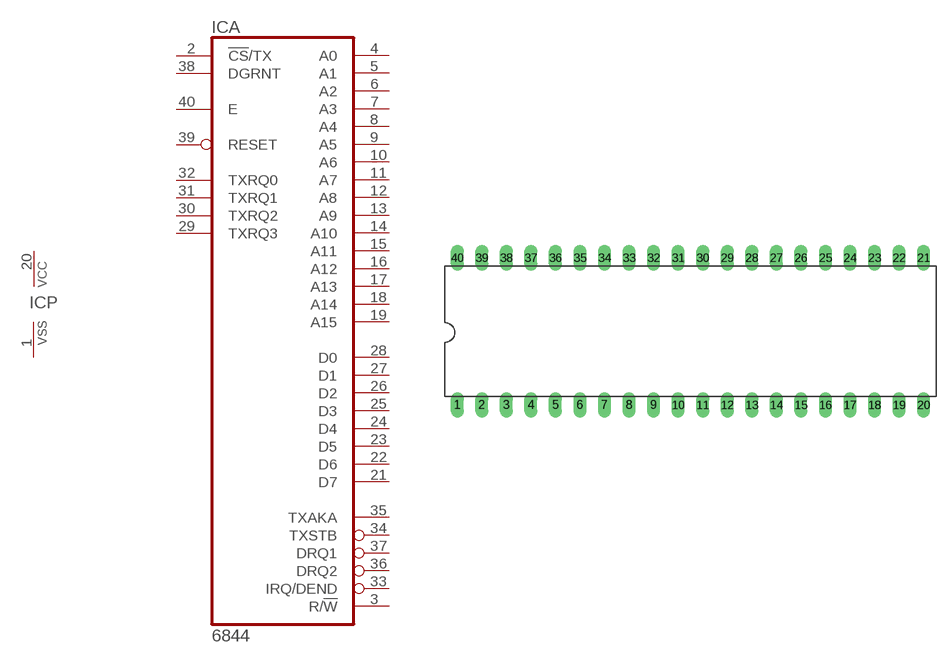
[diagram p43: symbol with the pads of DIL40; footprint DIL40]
Designator prefix IC; gates A=6844 P=PWRVSS

## 6844 (OC_FARNELL: unknown; OC_NEWARK: unknown)  [DIL40]
1  P:VSS  pwr
2  A:!CS!/TX  in
3  A:R/!W
4  A:A0
5  A:A1
6  A:A2
7  A:A3
8  A:A4
9  A:A5  out
10  A:A6  out
11  A:A7  out
12  A:A8  out
13  A:A9  out
14  A:A10  out
15  A:A11  out
16  A:A12  out
17  A:A13  out
18  A:A14  out
19  A:A15  out
20  P:VCC  pwr
21  A:D7
22  A:D6
23  A:D5
24  A:D4
25  A:D3
26  A:D2
27  A:D1
28  A:D0
29  A:TXRQ3  in
30  A:TXRQ2  in
31  A:TXRQ1  in
32  A:TXRQ0  in
33  A:IRQ/DEND  out
34  A:TXSTB  out
35  A:TXAKA  out
36  A:DRQ2  out
37  A:DRQ1  out
38  A:DGRNT  in
39  A:RESET  in
40  A:E  in

## Footprint DIL40 (pad centres in mm)
Dual In Line Package
drill 0.813 long: 1 -24.13,-7.62; 2 -21.59,-7.62; 3 -19.05,-7.62; 4 -16.51,-7.62; 5 -13.97,-7.62; 6 -11.43,-7.62; 7 -8.89,-7.62; 8 -6.35,-7.62; 9 -3.81,-7.62; 10 -1.27,-7.62; 11 1.27,-7.62; 12 3.81,-7.62; 13 6.35,-7.62; 14 8.89,-7.62; 15 11.43,-7.62; 16 13.97,-7.62; 17 16.51,-7.62; 18 19.05,-7.62; 19 21.59,-7.62; 20 24.13,-7.62; 21 24.13,7.62; 22 21.59,7.62; 23 19.05,7.62; 24 16.51,7.62; 25 13.97,7.62; 26 11.43,7.62; 27 8.89,7.62; 28 6.35,7.62; 29 3.81,7.62; 30 1.27,7.62; 31 -1.27,7.62; 32 -3.81,7.62; 33 -6.35,7.62; 34 -8.89,7.62; 35 -11.43,7.62; 36 -13.97,7.62; 37 -16.51,7.62; 38 -19.05,7.62; 39 -21.59,7.62; 40 -24.13,7.62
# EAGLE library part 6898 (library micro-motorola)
MICROCONTROLLER/MEMORY DEVICE

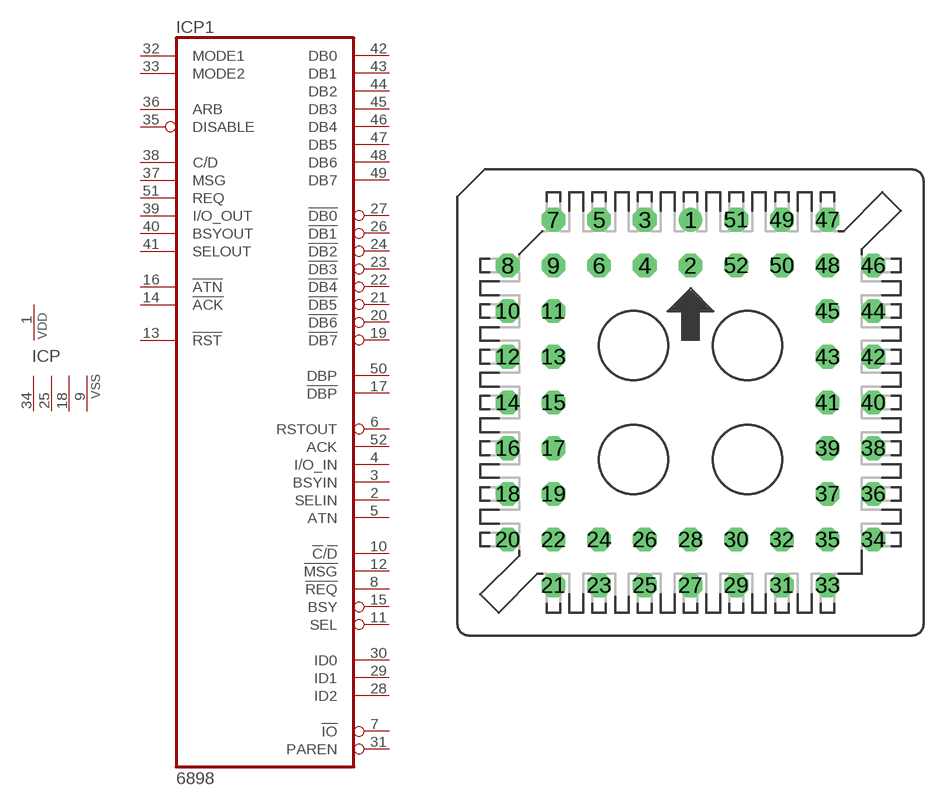
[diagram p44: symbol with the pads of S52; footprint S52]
Designator prefix IC; gates P=4VSSVDD P1=6898

## 6898 (OC_FARNELL: unknown; OC_NEWARK: unknown)  [S52]
1  P:VDD  pwr
2  P1:SELIN  out
3  P1:BSYIN  out
4  P1:I/O_IN  out
5  P1:ATN  out
6  P1:RSTOUT  out
7  P1:!IO
8  P1:!REQ  out
9  P:VSS  pwr
10  P1:!C!/!D  out
11  P1:SEL
12  P1:!MSG  out
13  P1:!RST  in
14  P1:!ACK  in
15  P1:BSY
16  P1:!ATN  in
17  P1:!DBP
18  P:VSS  pwr
19  P1:!DB7
20  P1:!DB6
21  P1:!DB5
22  P1:!DB4
23  P1:!DB3
24  P1:!DB2
25  P:VSS  pwr
26  P1:!DB1
27  P1:!DB0
28  P1:ID2
29  P1:ID1
30  P1:ID0
31  P1:PAREN
32  P1:MODE1  in
33  P1:MODE2  in
34  P:VSS  pwr
35  P1:DISABLE  in
36  P1:ARB  in
37  P1:MSG  in
38  P1:C/D  in
39  P1:I/O_OUT  in
40  P1:BSYOUT  in
41  P1:SELOUT  in
42  P1:DB0
43  P1:DB1
44  P1:DB2
45  P1:DB3
46  P1:DB4
47  P1:DB5
48  P1:DB6
49  P1:DB7
50  P1:DBP
51  P1:REQ  in
52  P1:ACK  out

## Footprint S52 (pad centres in mm)
PLCC SOCKET
drill 0.813 round: 1 0,10.16
drill 0.813 octagon: 2 0,7.62; 3 -2.54,10.16; 4 -2.54,7.62; 5 -5.08,10.16; 6 -5.08,7.62; 7 -7.62,10.16; 8 -10.16,7.62; 9 -7.62,7.62; 10 -10.16,5.08; 11 -7.62,5.08; 12 -10.16,2.54; 13 -7.62,2.54; 14 -10.16,0; 15 -7.62,0; 16 -10.16,-2.54; 17 -7.62,-2.54; 18 -10.16,-5.08; 19 -7.62,-5.08; 20 -10.16,-7.62; 21 -7.62,-10.16; 22 -7.62,-7.62; 23 -5.08,-10.16; 24 -5.08,-7.62; 25 -2.54,-10.16; 26 -2.54,-7.62; 27 0,-10.16; 28 0,-7.62; 29 2.54,-10.16; 30 2.54,-7.62; 31 5.08,-10.16; 32 5.08,-7.62; 33 7.62,-10.16; 34 10.16,-7.62; 35 7.62,-7.62; 36 10.16,-5.08; 37 7.62,-5.08; 38 10.16,-2.54; 39 7.62,-2.54; 40 10.16,0; 41 7.62,0; 42 10.16,2.54; 43 7.62,2.54; 44 10.16,5.08; 45 7.62,5.08; 46 10.16,7.62; 47 7.62,10.16; 48 7.62,7.62; 49 5.08,10.16; 50 5.08,7.62; 51 2.54,10.16; 52 2.54,7.62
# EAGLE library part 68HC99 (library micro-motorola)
MICROCONTROLLER/MEMORY DEVICE

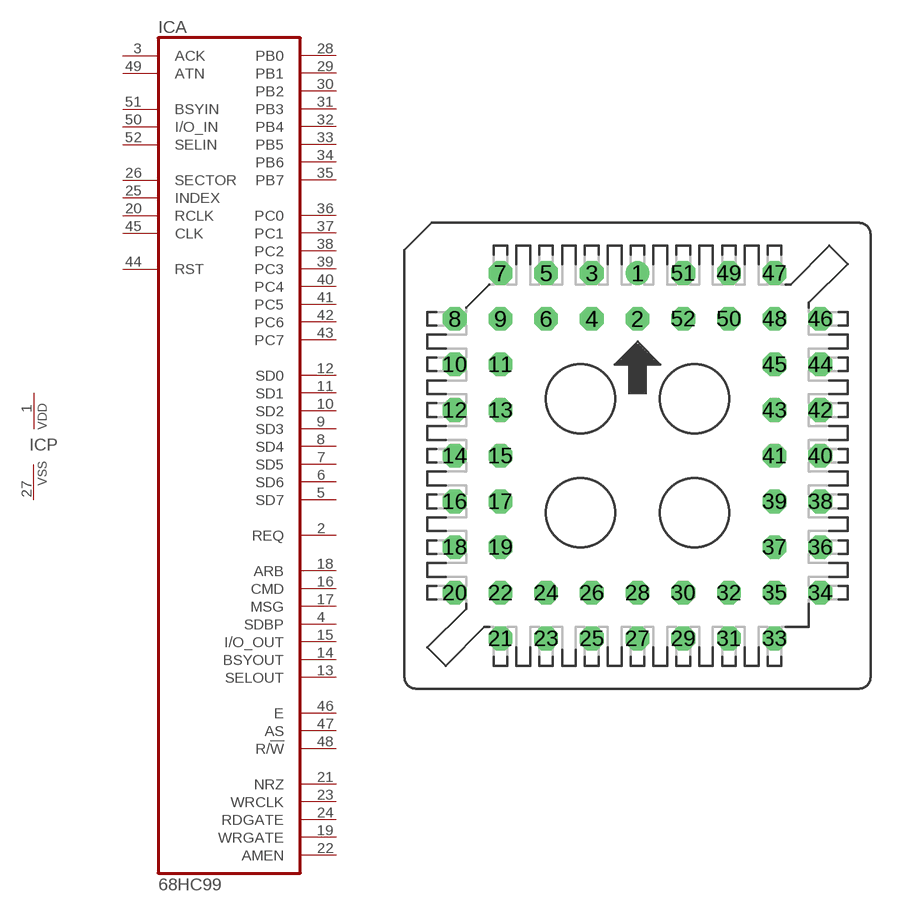
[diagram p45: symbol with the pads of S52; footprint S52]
Designator prefix IC; gates A=68HC99 P=VSSVDD

## 68HC99 (OC_FARNELL: unknown; OC_NEWARK: unknown)  [S52]
1  P:VDD  pwr
2  A:REQ  out
3  A:ACK  in
4  A:SDBP  out
5  A:SD7  out
6  A:SD6  out
7  A:SD5  out
8  A:SD4  out
9  A:SD3  out
10  A:SD2  out
11  A:SD1  out
12  A:SD0  out
13  A:SELOUT  out
14  A:BSYOUT  out
15  A:I/O_OUT  out
16  A:CMD  out
17  A:MSG  out
18  A:ARB  out
19  A:WRGATE  out
20  A:RCLK  in
21  A:NRZ
22  A:AMEN  out
23  A:WRCLK  out
24  A:RDGATE  out
25  A:INDEX  in
26  A:SECTOR  in
27  P:VSS  pwr
28  A:PB0
29  A:PB1
30  A:PB2
31  A:PB3
32  A:PB4
33  A:PB5
34  A:PB6
35  A:PB7
36  A:PC0
37  A:PC1
38  A:PC2
39  A:PC3
40  A:PC4
41  A:PC5
42  A:PC6
43  A:PC7
44  A:RST  in
45  A:CLK  in
46  A:E  out
47  A:AS  out
48  A:R/!W  out
49  A:ATN  in
50  A:I/O_IN  in
51  A:BSYIN  in
52  A:SELIN  in

## Footprint S52 (pad centres in mm)
PLCC SOCKET
drill 0.813 round: 1 0,10.16
drill 0.813 octagon: 2 0,7.62; 3 -2.54,10.16; 4 -2.54,7.62; 5 -5.08,10.16; 6 -5.08,7.62; 7 -7.62,10.16; 8 -10.16,7.62; 9 -7.62,7.62; 10 -10.16,5.08; 11 -7.62,5.08; 12 -10.16,2.54; 13 -7.62,2.54; 14 -10.16,0; 15 -7.62,0; 16 -10.16,-2.54; 17 -7.62,-2.54; 18 -10.16,-5.08; 19 -7.62,-5.08; 20 -10.16,-7.62; 21 -7.62,-10.16; 22 -7.62,-7.62; 23 -5.08,-10.16; 24 -5.08,-7.62; 25 -2.54,-10.16; 26 -2.54,-7.62; 27 0,-10.16; 28 0,-7.62; 29 2.54,-10.16; 30 2.54,-7.62; 31 5.08,-10.16; 32 5.08,-7.62; 33 7.62,-10.16; 34 10.16,-7.62; 35 7.62,-7.62; 36 10.16,-5.08; 37 7.62,-5.08; 38 10.16,-2.54; 39 7.62,-2.54; 40 10.16,0; 41 7.62,0; 42 10.16,2.54; 43 7.62,2.54; 44 10.16,5.08; 45 7.62,5.08; 46 10.16,7.62; 47 7.62,10.16; 48 7.62,7.62; 49 5.08,10.16; 50 5.08,7.62; 51 2.54,10.16; 52 2.54,7.62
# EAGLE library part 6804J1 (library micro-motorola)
MICROCONTROLLER/MEMORY DEVICE

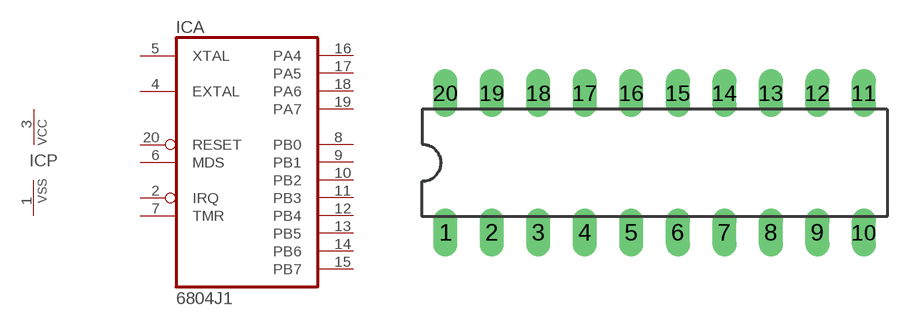
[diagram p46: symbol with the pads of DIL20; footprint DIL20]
Designator prefix IC; gates A=6804J1 P=PWRVSS

## 6804J1 (OC_FARNELL: unknown; OC_NEWARK: unknown)  [DIL20]
1  P:VSS  pwr
2  A:IRQ  in
3  P:VCC  pwr
4  A:EXTAL  in
5  A:XTAL  in
6  A:MDS  in
7  A:TMR  in
8  A:PB0
9  A:PB1
10  A:PB2
11  A:PB3
12  A:PB4
13  A:PB5
14  A:PB6
15  A:PB7
16  A:PA4
17  A:PA5
18  A:PA6
19  A:PA7
20  A:RESET  in

## Footprint DIL20 (pad centres in mm)
Dual In Line Package
drill 0.813 long: 1 -11.43,-3.81; 2 -8.89,-3.81; 3 -6.35,-3.81; 4 -3.81,-3.81; 5 -1.27,-3.81; 6 1.27,-3.81; 7 3.81,-3.81; 8 6.35,-3.81; 9 8.89,-3.81; 10 11.43,-3.81; 11 11.43,3.81; 12 8.89,3.81; 13 6.35,3.81; 14 3.81,3.81; 15 1.27,3.81; 16 -1.27,3.81; 17 -3.81,3.81; 18 -6.35,3.81; 19 -8.89,3.81; 20 -11.43,3.81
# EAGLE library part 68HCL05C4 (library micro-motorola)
MICROCONTROLLER/MEMORY DEVICE

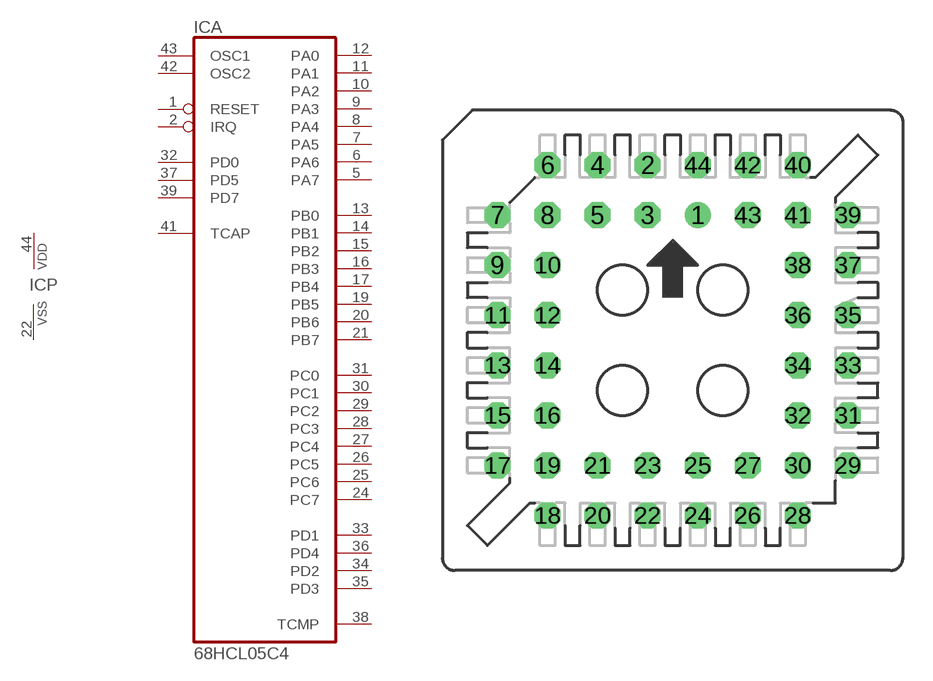
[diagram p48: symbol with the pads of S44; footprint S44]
Designator prefix IC; gates A=68HCL5C4 P=VSSVDD

## 68HCL05C4 (OC_FARNELL: unknown; OC_NEWARK: unknown)  [S44]
1  A:RESET  in
2  A:IRQ  in
5  A:PA7
6  A:PA6
7  A:PA5
8  A:PA4
9  A:PA3
10  A:PA2
11  A:PA1
12  A:PA0
13  A:PB0
14  A:PB1
15  A:PB2
16  A:PB3
17  A:PB4
19  A:PB5
20  A:PB6
21  A:PB7
22  P:VSS  pwr
24  A:PC7
25  A:PC6
26  A:PC5
27  A:PC4
28  A:PC3
29  A:PC2
30  A:PC1
31  A:PC0
32  A:PD0  in
33  A:PD1
34  A:PD2
35  A:PD3
36  A:PD4
37  A:PD5  in
38  A:TCMP  out
39  A:PD7  in
41  A:TCAP  in
42  A:OSC2  pas
43  A:OSC1  in
44  P:VDD  pwr

## Footprint S44 (pad centres in mm)
PLCC SOCKET
drill 0.813 round: 1 1.27,6.35
drill 0.813 octagon: 2 -1.27,8.89; 3 -1.27,6.35; 4 -3.81,8.89; 5 -3.81,6.35; 6 -6.35,8.89; 7 -8.89,6.35; 8 -6.35,6.35; 9 -8.89,3.81; 10 -6.35,3.81; 11 -8.89,1.27; 12 -6.35,1.27; 13 -8.89,-1.27; 14 -6.35,-1.27; 15 -8.89,-3.81; 16 -6.35,-3.81; 17 -8.89,-6.35; 18 -6.35,-8.89; 19 -6.35,-6.35; 20 -3.81,-8.89; 21 -3.81,-6.35; 22 -1.27,-8.89; 23 -1.27,-6.35; 24 1.27,-8.89; 25 1.27,-6.35; 26 3.81,-8.89; 27 3.81,-6.35; 28 6.35,-8.89; 29 8.89,-6.35; 30 6.35,-6.35; 31 8.89,-3.81; 32 6.35,-3.81; 33 8.89,-1.27; 34 6.35,-1.27; 35 8.89,1.27; 36 6.35,1.27; 37 8.89,3.81; 38 6.35,3.81; 39 8.89,6.35; 40 6.35,8.89; 41 6.35,6.35; 42 3.81,8.89; 43 3.81,6.35; 44 1.27,8.89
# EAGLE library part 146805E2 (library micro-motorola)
MICROCONTROLLER/MEMORY DEVICE

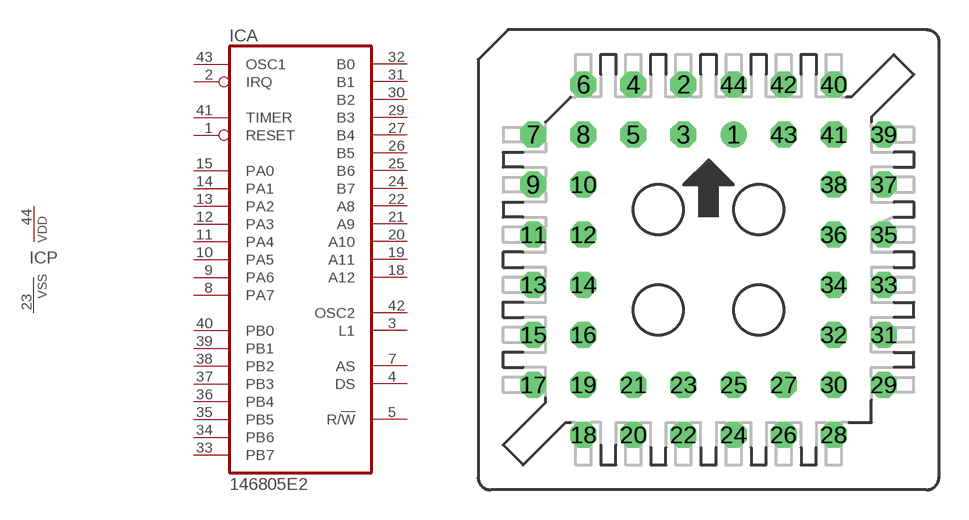
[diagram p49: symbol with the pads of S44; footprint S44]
Designator prefix IC; gates A=146805E2 P=VSSVDD

## 146805E2 (OC_FARNELL: unknown; OC_NEWARK: unknown)  [S44]
1  A:RESET  in
2  A:IRQ  in
3  A:L1  out
4  A:DS  out
5  A:R/!W  out
7  A:AS  out
8  A:PA7
9  A:PA6
10  A:PA5
11  A:PA4
12  A:PA3
13  A:PA2
14  A:PA1
15  A:PA0
18  A:A12  out
19  A:A11  out
20  A:A10  out
21  A:A9  out
22  A:A8  out
23  P:VSS  pwr
24  A:B7
25  A:B6
26  A:B5
27  A:B4
29  A:B3
30  A:B2
31  A:B1
32  A:B0
33  A:PB7
34  A:PB6
35  A:PB5
36  A:PB4
37  A:PB3
38  A:PB2
39  A:PB1
40  A:PB0
41  A:TIMER  in
42  A:OSC2  out
43  A:OSC1  in
44  P:VDD  pwr

## Footprint S44 (pad centres in mm)
PLCC SOCKET
drill 0.813 round: 1 1.27,6.35
drill 0.813 octagon: 2 -1.27,8.89; 3 -1.27,6.35; 4 -3.81,8.89; 5 -3.81,6.35; 6 -6.35,8.89; 7 -8.89,6.35; 8 -6.35,6.35; 9 -8.89,3.81; 10 -6.35,3.81; 11 -8.89,1.27; 12 -6.35,1.27; 13 -8.89,-1.27; 14 -6.35,-1.27; 15 -8.89,-3.81; 16 -6.35,-3.81; 17 -8.89,-6.35; 18 -6.35,-8.89; 19 -6.35,-6.35; 20 -3.81,-8.89; 21 -3.81,-6.35; 22 -1.27,-8.89; 23 -1.27,-6.35; 24 1.27,-8.89; 25 1.27,-6.35; 26 3.81,-8.89; 27 3.81,-6.35; 28 6.35,-8.89; 29 8.89,-6.35; 30 6.35,-6.35; 31 8.89,-3.81; 32 6.35,-3.81; 33 8.89,-1.27; 34 6.35,-1.27; 35 8.89,1.27; 36 6.35,1.27; 37 8.89,3.81; 38 6.35,3.81; 39 8.89,6.35; 40 6.35,8.89; 41 6.35,6.35; 42 3.81,8.89; 43 3.81,6.35; 44 1.27,8.89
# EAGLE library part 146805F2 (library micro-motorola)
MICROCONTROLLER/MEMORY DEVICE

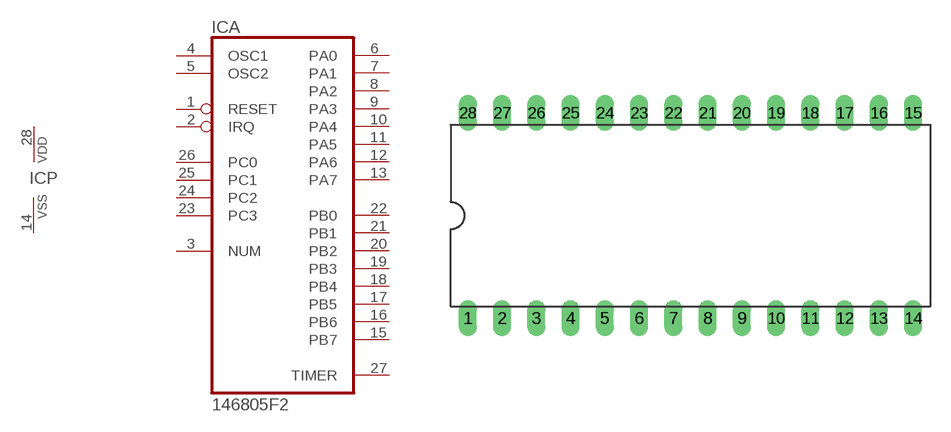
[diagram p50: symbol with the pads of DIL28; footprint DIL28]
Designator prefix IC; gates A=146805F2 P=VSSVDD

## 146805F2 (OC_FARNELL: unknown; OC_NEWARK: unknown)  [DIL28]
1  A:RESET  in
2  A:IRQ  in
3  A:NUM  in
4  A:OSC1  in
5  A:OSC2  pas
6  A:PA0
7  A:PA1
8  A:PA2
9  A:PA3
10  A:PA4
11  A:PA5
12  A:PA6
13  A:PA7
14  P:VSS  pwr
15  A:PB7
16  A:PB6
17  A:PB5
18  A:PB4
19  A:PB3
20  A:PB2
21  A:PB1
22  A:PB0
23  A:PC3  in
24  A:PC2  in
25  A:PC1  in
26  A:PC0  in
27  A:TIMER
28  P:VDD  pwr

## Footprint DIL28 (pad centres in mm)
Dual In Line Package
drill 0.813 long: 1 -16.51,-7.62; 2 -13.97,-7.62; 3 -11.43,-7.62; 4 -8.89,-7.62; 5 -6.35,-7.62; 6 -3.81,-7.62; 7 -1.27,-7.62; 8 1.27,-7.62; 9 3.81,-7.62; 10 6.35,-7.62; 11 8.89,-7.62; 12 11.43,-7.62; 13 13.97,-7.62; 14 16.51,-7.62; 15 16.51,7.62; 16 13.97,7.62; 17 11.43,7.62; 18 8.89,7.62; 19 6.35,7.62; 20 3.81,7.62; 21 1.27,7.62; 22 -1.27,7.62; 23 -3.81,7.62; 24 -6.35,7.62; 25 -8.89,7.62; 26 -11.43,7.62; 27 -13.97,7.62; 28 -16.51,7.62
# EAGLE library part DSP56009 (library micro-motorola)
MICROCONTROLLER/MEMORY DEVICE

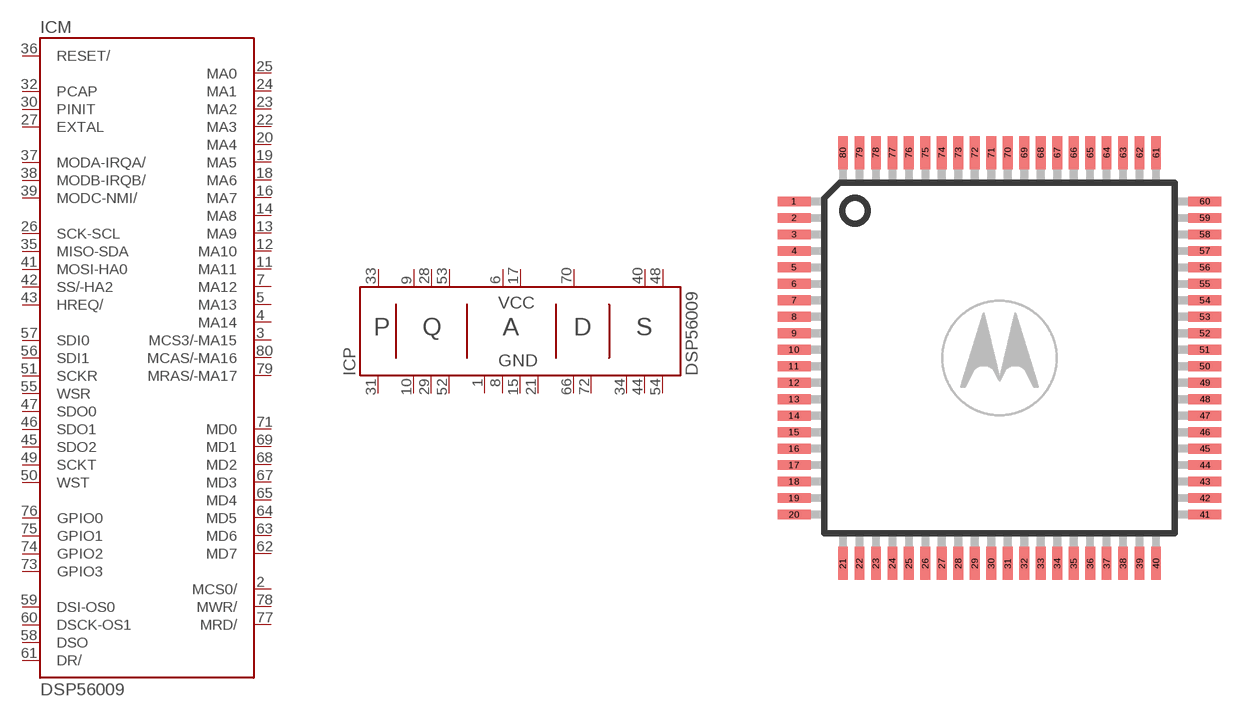
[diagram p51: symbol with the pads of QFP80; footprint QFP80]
Designator prefix IC; gates M=DSP56009 P=P56009

## DSP56009 (OC_FARNELL: unknown; OC_NEWARK: unknown)  [QFP80]
1  P:GNDA  pwr
2  M:MCS0/  out
3  M:MCS3/-MA15  out
4  M:MA14  out
5  M:MA13  out
6  P:VCCA  pwr
7  M:MA12  out
8  P:GNDA  pwr
9  P:VCCQ  pwr
10  P:GNDQ  pwr
11  M:MA11  out
12  M:MA10  out
13  M:MA9  out
14  M:MA8  out
15  P:GNDA  pwr
16  M:MA7  out
17  P:VCCA  pwr
18  M:MA6  out
19  M:MA5  out
20  M:MA4  out
21  P:GNDA  pwr
22  M:MA3  out
23  M:MA2  out
24  M:MA1  out
25  M:MA0  out
26  M:SCK-SCL
27  M:EXTAL  in
28  P:VCCQ  pwr
29  P:GNDQ  pwr
30  M:PINIT  in
31  P:GNDP  pwr
32  M:PCAP  in
33  P:VCCP  pwr
34  P:GNDS  pwr
35  M:MISO-SDA
36  M:RESET/  in
37  M:MODA-IRQA/  in
38  M:MODB-IRQB/  in
39  M:MODC-NMI/  in
40  P:VCCS  pwr
41  M:MOSI-HA0
42  M:SS/-HA2  in
43  M:HREQ/
44  P:GNDS  pwr
45  M:SDO2  out
46  M:SDO1  out
47  M:SDO0  out
48  P:VCCS  pwr
49  M:SCKT
50  M:WST
51  M:SCKR
52  P:GNDQ  pwr
53  P:VCCQ  pwr
54  P:GNDS  pwr
55  M:WSR
56  M:SDI1  in
57  M:SDI0  in
58  M:DSO  out
59  M:DSI-OS0
60  M:DSCK-OS1
61  M:DR/  in
62  M:MD7
63  M:MD6
64  M:MD5
65  M:MD4
66  P:GNDD  pwr
67  M:MD3
68  M:MD2
69  M:MD1
70  P:VCCD  pwr
71  M:MD0
72  P:GNDD  pwr
73  M:GPIO3
74  M:GPIO2
75  M:GPIO1
76  M:GPIO0
77  M:MRD/  out
78  M:MWR/  out
79  M:MRAS/-MA17  out
80  M:MCAS/-MA16  out

## Footprint QFP80 (pad centres in mm)
Quad Flat Pack
smd 1.3 x 0.38: 1 -8.1,6.175; 2 -8.1,5.525; 3 -8.1,4.875; 4 -8.1,4.225; 5 -8.1,3.575; 6 -8.1,2.925; 7 -8.1,2.275; 8 -8.1,1.625; 9 -8.1,0.975; 10 -8.1,0.325; 11 -8.1,-0.325; 12 -8.1,-0.975; 13 -8.1,-1.625; 14 -8.1,-2.275; 15 -8.1,-2.925; 16 -8.1,-3.575; 17 -8.1,-4.225; 18 -8.1,-4.875; 19 -8.1,-5.525; 20 -8.1,-6.175; 41 8.1,-6.175; 42 8.1,-5.525; 43 8.1,-4.875; 44 8.1,-4.225; 45 8.1,-3.575; 46 8.1,-2.925; 47 8.1,-2.275; 48 8.1,-1.625; 49 8.1,-0.975; 50 8.1,-0.325; 51 8.1,0.325; 52 8.1,0.975; 53 8.1,1.625; 54 8.1,2.275; 55 8.1,2.925; 56 8.1,3.575; 57 8.1,4.225; 58 8.1,4.875; 59 8.1,5.525; 60 8.1,6.175
smd 0.38 x 1.3: 21 -6.175,-8.1; 22 -5.525,-8.1; 23 -4.875,-8.1; 24 -4.225,-8.1; 25 -3.575,-8.1; 26 -2.925,-8.1; 27 -2.275,-8.1; 28 -1.625,-8.1; 29 -0.975,-8.1; 30 -0.325,-8.1; 31 0.325,-8.1; 32 0.975,-8.1; 33 1.625,-8.1; 34 2.275,-8.1; 35 2.925,-8.1; 36 3.575,-8.1; 37 4.225,-8.1; 38 4.875,-8.1; 39 5.525,-8.1; 40 6.175,-8.1; 61 6.175,8.1; 62 5.525,8.1; 63 4.875,8.1; 64 4.225,8.1; 65 3.575,8.1; 66 2.925,8.1; 67 2.275,8.1; 68 1.625,8.1; 69 0.975,8.1; 70 0.325,8.1; 71 -0.325,8.1; 72 -0.975,8.1; 73 -1.625,8.1; 74 -2.275,8.1; 75 -2.925,8.1; 76 -3.575,8.1; 77 -4.225,8.1; 78 -4.875,8.1; 79 -5.525,8.1; 80 -6.175,8.1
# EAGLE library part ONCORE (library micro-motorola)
MICROCONTROLLER/MEMORY DEVICE

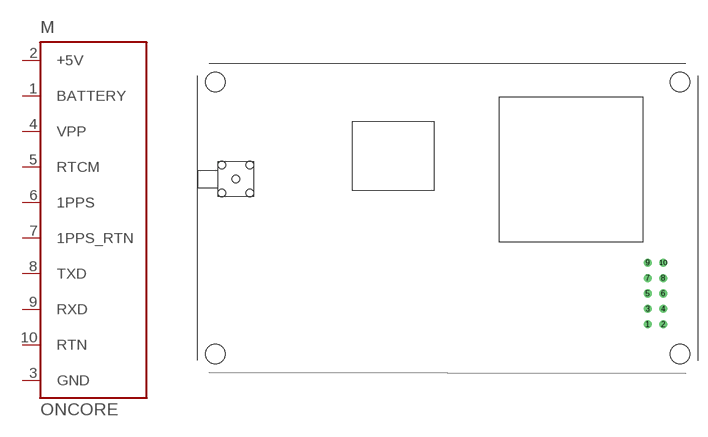
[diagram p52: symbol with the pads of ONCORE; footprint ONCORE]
Designator prefix M

## ONCORE (OC_FARNELL: unknown; OC_NEWARK: unknown)  [ONCORE]
1  BATTERY  in
2  +5V  pwr
3  GND  pwr
4  VPP  in
5  RTCM  in
6  1PPS  in
7  1PPS_RTN  out
8  TXD  out
9  RXD  in
10  RTN  out

## Footprint ONCORE (pad centres in mm)
Oncore Receiver
drill 0.813 round: 1 71.2,4.9; 2 73.74,4.9; 3 71.2,7.44; 4 73.74,7.44; 5 71.2,9.98; 6 73.74,9.98; 7 71.2,12.52; 8 73.74,12.52; 9 71.2,15.06; 10 73.74,15.06
hole 3.2 at 0,0
hole 3.2 at 76.55,0
hole 3.2 at 76.55,44.8
hole 3.2 at 0,44.8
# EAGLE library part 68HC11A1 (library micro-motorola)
MICROCONTROLLER/MEMORY DEVICE

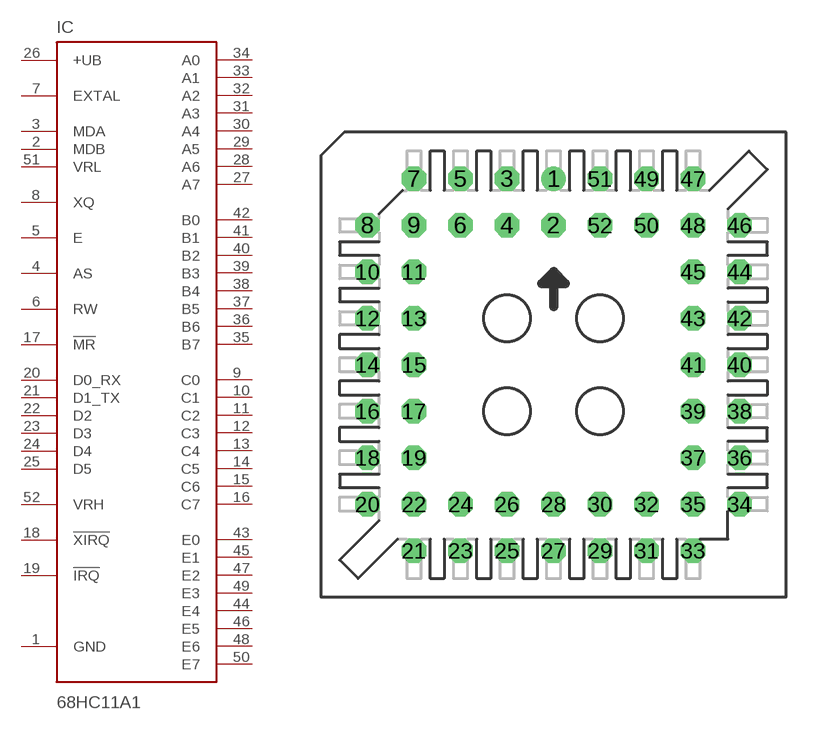
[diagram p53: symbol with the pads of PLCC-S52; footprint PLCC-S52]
Designator prefix IC

## 68HC11A1 (MPN: MC68HC11A1CFNE3R; OC_FARNELL: 1821771; OC_NEWARK: 81K2780)  [PLCC-S52]
1  GND
2  MDB
3  MDA
4  AS
5  E  out
6  RW
7  EXTAL
8  XQ  out
9  C0
10  C1
11  C2
12  C3
13  C4
14  C5
15  C6
16  C7
17  !MR
18  !XIRQ  in
19  !IRQ  in
20  D0_RX
21  D1_TX
22  D2
23  D3
24  D4
25  D5
26  +UB
27  A7
28  A6  out
29  A5  out
30  A4  out
31  A3  out
32  A2  in
33  A1  in
34  A0  in
35  B7  out
36  B6  out
37  B5  out
38  B4  out
39  B3  out
40  B2  out
41  B1  out
42  B0  out
43  E0  in
44  E4  in
45  E1  in
46  E5  in
47  E2  in
48  E6  in
49  E3  in
50  E7  in
51  VRL  in
52  VRH  in

## Footprint PLCC-S52 (pad centres in mm)
Plastic Leaded Chip Carrier Socked
drill 0.813 round: 1 0,10.16
drill 0.813 octagon: 2 0,7.62; 3 -2.54,10.16; 4 -2.54,7.62; 5 -5.08,10.16; 6 -5.08,7.62; 7 -7.62,10.16; 8 -10.16,7.62; 9 -7.62,7.62; 10 -10.16,5.08; 11 -7.62,5.08; 12 -10.16,2.54; 13 -7.62,2.54; 14 -10.16,0; 15 -7.62,0; 16 -10.16,-2.54; 17 -7.62,-2.54; 18 -10.16,-5.08; 19 -7.62,-5.08; 20 -10.16,-7.62; 21 -7.62,-10.16; 22 -7.62,-7.62; 23 -5.08,-10.16; 24 -5.08,-7.62; 25 -2.54,-10.16; 26 -2.54,-7.62; 27 0,-10.16; 28 0,-7.62; 29 2.54,-10.16; 30 2.54,-7.62; 31 5.08,-10.16; 32 5.08,-7.62; 33 7.62,-10.16; 34 10.16,-7.62; 35 7.62,-7.62; 36 10.16,-5.08; 37 7.62,-5.08; 38 10.16,-2.54; 39 7.62,-2.54; 40 10.16,0; 41 7.62,0; 42 10.16,2.54; 43 7.62,2.54; 44 10.16,5.08; 45 7.62,5.08; 46 10.16,7.62; 47 7.62,10.16; 48 7.62,7.62; 49 5.08,10.16; 50 5.08,7.62; 51 2.54,10.16; 52 2.54,7.62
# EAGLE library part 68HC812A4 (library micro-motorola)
MICROCONTROLLER/MEMORY DEVICE

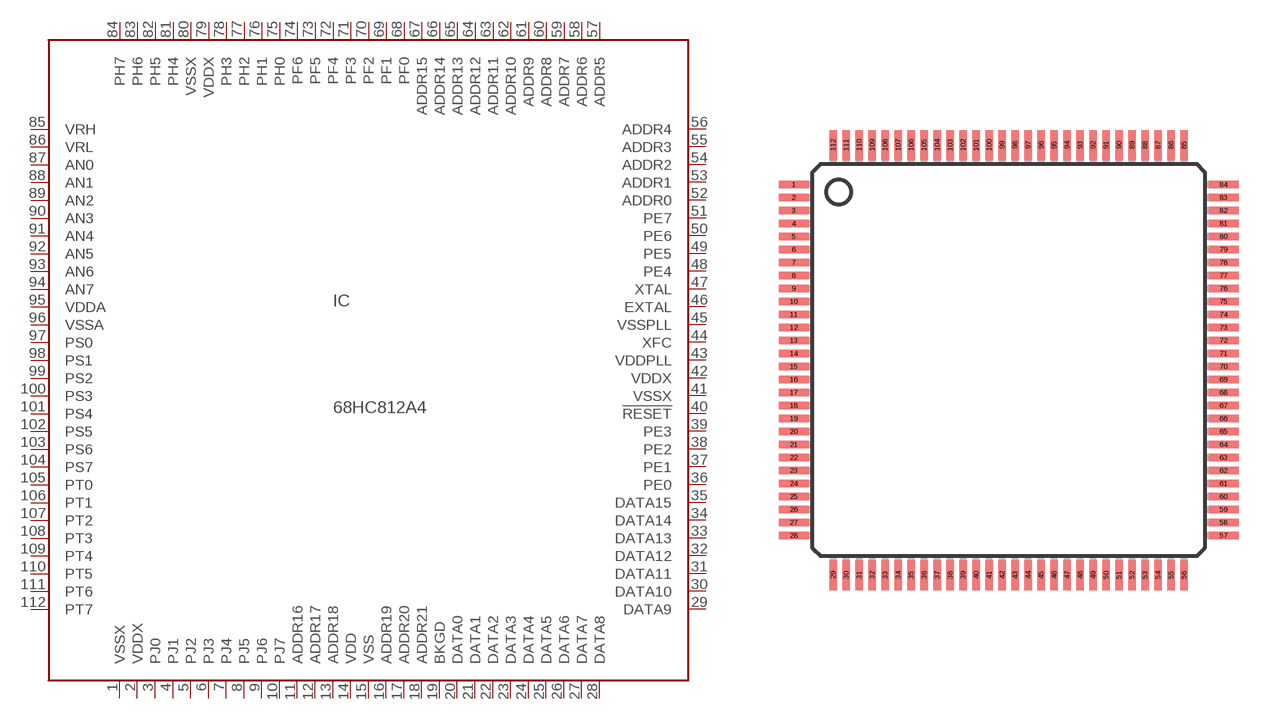
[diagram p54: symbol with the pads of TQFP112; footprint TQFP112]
Designator prefix IC

## 68HC812A4 (MF: MOTOROLA; MPN: MC68HC812A4CPV8; OC_FARNELL: unknown; OC_NEWARK: 70C4455)  [TQFP112]
1  VSSX  pwr
2  VDDX  pwr
3  PJ0
4  PJ1
5  PJ2
6  PJ3
7  PJ4
8  PJ5
9  PJ6
10  PJ7
11  ADDR16
12  ADDR17
13  ADDR18
14  VDD  pwr
15  VSS  pwr
16  ADDR19
17  ADDR20
18  ADDR21
19  BKGD  in
20  DATA0
21  DATA1
22  DATA2
23  DATA3
24  DATA4
25  DATA5
26  DATA6
27  DATA7
28  DATA8
29  DATA9
30  DATA10
31  DATA11
32  DATA12
33  DATA13
34  DATA14
35  DATA15
36  PE0  in
37  PE1  in
38  PE2
39  PE3
40  !RESET  in
41  VSSX  pwr
42  VDDX  pwr
43  VDDPLL
44  XFC
45  VSSPLL
46  EXTAL  in
47  XTAL  in
48  PE4
49  PE5  in
50  PE6  in
51  PE7
52  ADDR0
53  ADDR1
54  ADDR2
55  ADDR3
56  ADDR4
57  ADDR5
58  ADDR6
59  ADDR7
60  ADDR8
61  ADDR9
62  ADDR10
63  ADDR11
64  ADDR12
65  ADDR13
66  ADDR14
67  ADDR15
68  PF0
69  PF1
70  PF2
71  PF3
72  PF4
73  PF5
74  PF6
75  PH0
76  PH1
77  PH2
78  PH3
79  VDDX  pwr
80  VSSX  pwr
81  PH4
82  PH5
83  PH6
84  PH7
85  VRH
86  VRL
87  AN0  in
88  AN1  in
89  AN2  in
90  AN3  in
91  AN4  in
92  AN5  in
93  AN6  in
94  AN7  in
95  VDDA  pwr
96  VSSA  pwr
97  PS0
98  PS1
99  PS2
100  PS3
101  PS4
102  PS5
103  PS6
104  PS7
105  PT0
106  PT1
107  PT2
108  PT3
109  PT4
110  PT5
111  PT6
112  PT7

## Footprint TQFP112 (pad centres in mm)
Thin Quad Flat Pack 112-Pin LQFP (Case no. 987) 9S12A256DGV1.pdf
smd 1.5 x 0.37: 1 -10.75,8.775; 2 -10.75,8.125; 3 -10.75,7.475; 4 -10.75,6.825; 5 -10.75,6.175; 6 -10.75,5.525; 7 -10.75,4.875; 8 -10.75,4.225; 9 -10.75,3.575; 10 -10.75,2.925; 11 -10.75,2.275; 12 -10.75,1.625; 13 -10.75,0.975; 14 -10.75,0.325; 15 -10.75,-0.325; 16 -10.75,-0.975; 17 -10.75,-1.625; 18 -10.75,-2.275; 19 -10.75,-2.925; 20 -10.75,-3.575; 21 -10.75,-4.225; 22 -10.75,-4.875; 23 -10.75,-5.525; 24 -10.75,-6.175; 25 -10.75,-6.825; 26 -10.75,-7.475; 27 -10.75,-8.125; 28 -10.75,-8.775; 57 10.75,-8.775; 58 10.75,-8.125; 59 10.75,-7.475; 60 10.75,-6.825; 61 10.75,-6.175; 62 10.75,-5.525; 63 10.75,-4.875; 64 10.75,-4.225; 65 10.75,-3.575; 66 10.75,-2.925; 67 10.75,-2.275; 68 10.75,-1.625; 69 10.75,-0.975; 70 10.75,-0.325; 71 10.75,0.325; 72 10.75,0.975; 73 10.75,1.625; 74 10.75,2.275; 75 10.75,2.925; 76 10.75,3.575; 77 10.75,4.225; 78 10.75,4.875; 79 10.75,5.525; 80 10.75,6.175; 81 10.75,6.825; 82 10.75,7.475; 83 10.75,8.125; 84 10.75,8.775
smd 0.37 x 1.5: 29 -8.775,-10.75; 30 -8.125,-10.75; 31 -7.475,-10.75; 32 -6.825,-10.75; 33 -6.175,-10.75; 34 -5.525,-10.75; 35 -4.875,-10.75; 36 -4.225,-10.75; 37 -3.575,-10.75; 38 -2.925,-10.75; 39 -2.275,-10.75; 40 -1.625,-10.75; 41 -0.975,-10.75; 42 -0.325,-10.75; 43 0.325,-10.75; 44 0.975,-10.75; 45 1.625,-10.75; 46 2.275,-10.75; 47 2.925,-10.75; 48 3.575,-10.75; 49 4.225,-10.75; 50 4.875,-10.75; 51 5.525,-10.75; 52 6.175,-10.75; 53 6.825,-10.75; 54 7.475,-10.75; 55 8.125,-10.75; 56 8.775,-10.75; 85 8.775,10.75; 86 8.125,10.75; 87 7.475,10.75; 88 6.825,10.75; 89 6.175,10.75; 90 5.525,10.75; 91 4.875,10.75; 92 4.225,10.75; 93 3.575,10.75; 94 2.925,10.75; 95 2.275,10.75; 96 1.625,10.75; 97 0.975,10.75; 98 0.325,10.75; 99 -0.325,10.75; 100 -0.975,10.75; 101 -1.625,10.75; 102 -2.275,10.75; 103 -2.925,10.75; 104 -3.575,10.75; 105 -4.225,10.75; 106 -4.875,10.75; 107 -5.525,10.75; 108 -6.175,10.75; 109 -6.825,10.75; 110 -7.475,10.75; 111 -8.125,10.75; 112 -8.775,10.75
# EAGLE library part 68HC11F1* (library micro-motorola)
HIGH-PERFORMANCE MICROCONTROLLER UNIT (MCU) source MC68HC11F1.pdf

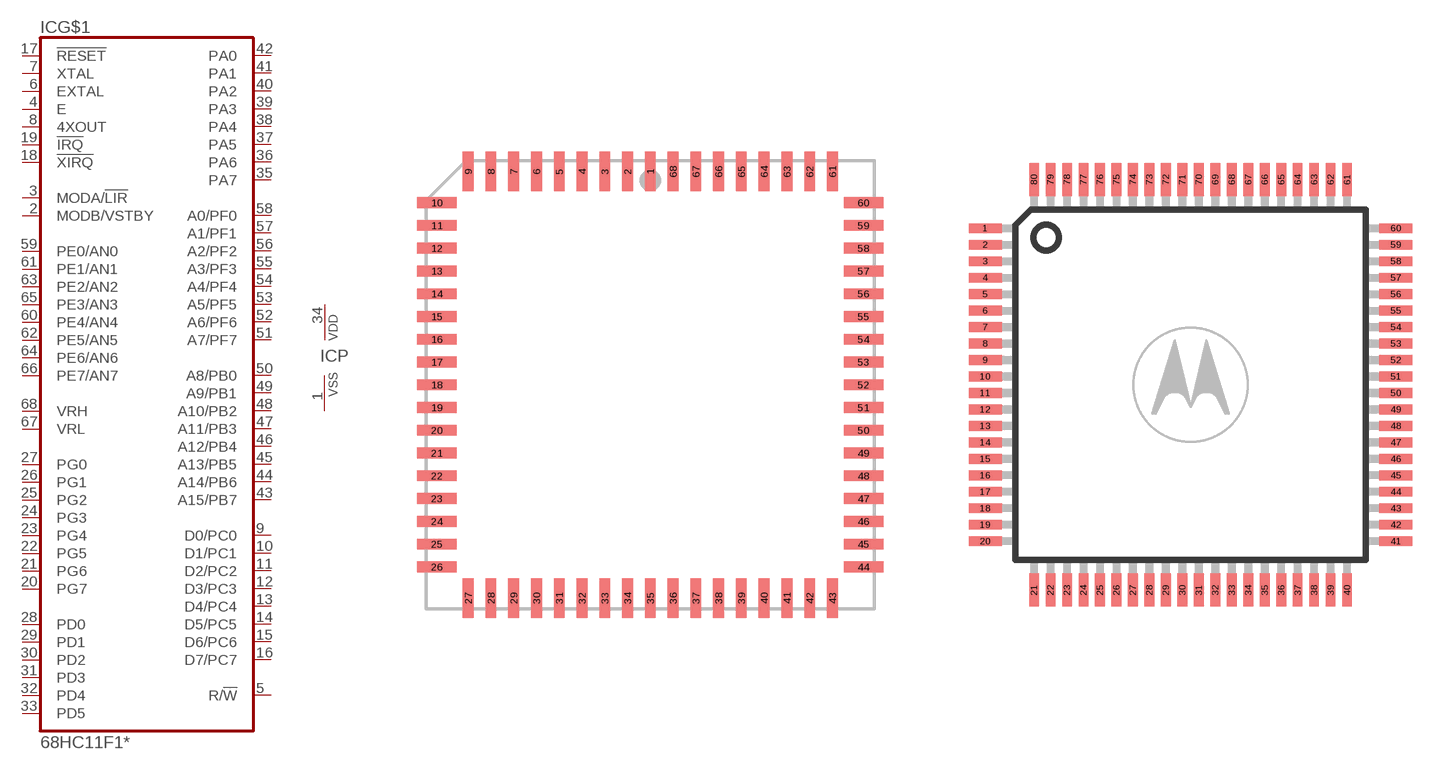
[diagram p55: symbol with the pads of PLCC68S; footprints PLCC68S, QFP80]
Designator prefix IC; gates G$1=68HC11F1 P=VSSVDD

## 68HC11F1CFN2 (MF: MOTOROLA; MPN: MC68HC11F1CFN2; OC_FARNELL: unknown; OC_NEWARK: 95B4396), 68HC11F1MFN2 (OC_FARNELL: unknown; OC_NEWARK: unknown), 68HC11F1VFN2 (OC_FARNELL: unknown; OC_NEWARK: unknown)  [PLCC68S]
1  P:VSS  pwr
2  G$1:MODB/VSTBY  in
3  G$1:MODA/!LIR
4  G$1:E  out
5  G$1:R/!W
6  G$1:EXTAL  in
7  G$1:XTAL  out
8  G$1:4XOUT  out
9  G$1:D0/PC0  hiz
10  G$1:D1/PC1  hiz
11  G$1:D2/PC2  hiz
12  G$1:D3/PC3  hiz
13  G$1:D4/PC4  hiz
14  G$1:D5/PC5  hiz
15  G$1:D6/PC6  hiz
16  G$1:D7/PC7  hiz
17  G$1:!RESET
18  G$1:!XIRQ  in
19  G$1:!IRQ  in
20  G$1:PG7
21  G$1:PG6
22  G$1:PG5
23  G$1:PG4
24  G$1:PG3
25  G$1:PG2
26  G$1:PG1
27  G$1:PG0
28  G$1:PD0
29  G$1:PD1
30  G$1:PD2
31  G$1:PD3
32  G$1:PD4
33  G$1:PD5
34  P:VDD  pwr
35  G$1:PA7
36  G$1:PA6
37  G$1:PA5
38  G$1:PA4
39  G$1:PA3
40  G$1:PA2
41  G$1:PA1
42  G$1:PA0
43  G$1:A15/PB7  out
44  G$1:A14/PB6  out
45  G$1:A13/PB5  out
46  G$1:A12/PB4  out
47  G$1:A11/PB3  out
48  G$1:A10/PB2  out
49  G$1:A9/PB1  out
50  G$1:A8/PB0  out
51  G$1:A7/PF7  out
52  G$1:A6/PF6  out
53  G$1:A5/PF5  out
54  G$1:A4/PF4  out
55  G$1:A3/PF3  out
56  G$1:A2/PF2  out
57  G$1:A1/PF1  out
58  G$1:A0/PF0  out
59  G$1:PE0/AN0  in
60  G$1:PE4/AN4  in
61  G$1:PE1/AN1  in
62  G$1:PE5/AN5  in
63  G$1:PE2/AN2  in
64  G$1:PE6/AN6  in
65  G$1:PE3/AN3  in
66  G$1:PE7/AN7  in
67  G$1:VRL  in
68  G$1:VRH  in

## 68HC11F1CPU2 (OC_FARNELL: unknown; OC_NEWARK: unknown), 68HC11F1MPU2 (OC_FARNELL: unknown; OC_NEWARK: unknown), 68HC11F1VPU2 (OC_FARNELL: unknown; OC_NEWARK: unknown)  [QFP80]
3  G$1:A14/PB6  out
4  G$1:A13/PB5  out
5  G$1:A12/PB4  out
6  G$1:A11/PB3  out
7  G$1:A10/PB2  out
8  G$1:A9/PB1  out
9  G$1:A8/PB0  out
10  G$1:A7/PF7  out
11  G$1:A6/PF6  out
12  G$1:A5/PF5  out
13  G$1:A4/PF4  out
14  G$1:A3/PF3  out
15  G$1:A2/PF2  out
16  G$1:A1/PF1  out
17  G$1:A0/PF0  out
18  G$1:PE0/AN0  in
19  G$1:PE4/AN4  in
23  G$1:PE1/AN1  in
24  G$1:PE5/AN5  in
25  G$1:PE2/AN2  in
26  G$1:PE6/AN6  in
27  G$1:PE3/AN3  in
28  G$1:PE7/AN7  in
29  G$1:VRL  in
30  G$1:VRH  in
31  P:VSS  pwr
32  G$1:MODB/VSTBY  in
33  G$1:MODA/!LIR
34  G$1:E  out
35  G$1:R/!W
36  G$1:EXTAL  in
37  G$1:XTAL  out
39  G$1:4XOUT  out
40  G$1:D0/PC0  hiz
43  G$1:D1/PC1  hiz
44  G$1:D2/PC2  hiz
45  G$1:D3/PC3  hiz
46  G$1:D4/PC4  hiz
47  G$1:D5/PC5  hiz
48  G$1:D6/PC6  hiz
49  G$1:D7/PC7  hiz
50  G$1:!RESET
51  G$1:!XIRQ  in
52  G$1:!IRQ  in
53  G$1:PG7
54  G$1:PG6
55  G$1:PG5
56  G$1:PG4
57  G$1:PG3
58  G$1:PG2
59  G$1:PG1
62  G$1:PG0
63  G$1:PD0
64  G$1:PD1
65  G$1:PD2
66  G$1:PD3
67  G$1:PD4
68  G$1:PD5
69  P:VDD  pwr
70  G$1:PA7
71  G$1:PA6
72  G$1:PA5
73  G$1:PA4
74  G$1:PA3
75  G$1:PA2
76  G$1:PA1
77  G$1:PA0
78  G$1:A15/PB7  out

## 68HC11F1CPU3 (OC_FARNELL: unknown; OC_NEWARK: unknown), 68HC11F1MPU3 (OC_FARNELL: unknown; OC_NEWARK: unknown), 68HC11F1VPU3 (OC_FARNELL: unknown; OC_NEWARK: unknown)  [QFP80]
Pads as for QFP80

## 68HC11F1CPU4 (OC_FARNELL: unknown; OC_NEWARK: unknown), 68HC11F1VPU4 (OC_FARNELL: unknown; OC_NEWARK: unknown)  [QFP80]
Pads as for QFP80

## 68HC11F1CFN3 (MF: MOTOROLA; MPN: MC68HC11F1CFN3; OC_FARNELL: unknown; OC_NEWARK: 07F5741), 68HC11F1MFN3 (MPN: MC68HC11F1CFN3R2; OC_FARNELL: unknown; OC_NEWARK: 07F5742), 68HC11F1VFN3 (OC_FARNELL: unknown; OC_NEWARK: unknown)  [PLCC68S]
Pads as for PLCC68S

## 68HC11F1CFN4 (MF: MOTOROLA; MPN: MC68HC11F1CFN4; OC_FARNELL: unknown; OC_NEWARK: 07F5743), 68HC11F1VFN4 (MF: MOTOROLA; MPN: MC68HC11F1MFN4; OC_FARNELL: unknown; OC_NEWARK: 92B3680)  [PLCC68S]
Pads as for PLCC68S

## 68HC11F1FN3-S (OC_FARNELL: unknown; OC_NEWARK: unknown)  [S68]
Pads as for PLCC68S

## Footprint PLCC68S (pad centres in mm)
PLASTIC LEADED CHIP CARRIER square
smd 0.6 x 2.2: 1 0,11.9; 2 -1.27,11.9; 3 -2.54,11.9; 4 -3.81,11.9; 5 -5.08,11.9; 6 -6.35,11.9; 7 -7.62,11.9; 8 -8.89,11.9; 9 -10.16,11.9; 27 -10.16,-11.9; 28 -8.89,-11.9; 29 -7.62,-11.9; 30 -6.35,-11.9; 31 -5.08,-11.9; 32 -3.81,-11.9; 33 -2.54,-11.9; 34 -1.27,-11.9; 35 0,-11.9; 36 1.27,-11.9; 37 2.54,-11.9; 38 3.81,-11.9; 39 5.08,-11.9; 40 6.35,-11.9; 41 7.62,-11.9; 42 8.89,-11.9; 43 10.16,-11.9; 61 10.16,11.9; 62 8.89,11.9; 63 7.62,11.9; 64 6.35,11.9; 65 5.08,11.9; 66 3.81,11.9; 67 2.54,11.9; 68 1.27,11.9
smd 2.2 x 0.6: 10 -11.9,10.16; 11 -11.9,8.89; 12 -11.9,7.62; 13 -11.9,6.35; 14 -11.9,5.08; 15 -11.9,3.81; 16 -11.9,2.54; 17 -11.9,1.27; 18 -11.9,0; 19 -11.9,-1.27; 20 -11.9,-2.54; 21 -11.9,-3.81; 22 -11.9,-5.08; 23 -11.9,-6.35; 24 -11.9,-7.62; 25 -11.9,-8.89; 26 -11.9,-10.16; 44 11.9,-10.16; 45 11.9,-8.89; 46 11.9,-7.62; 47 11.9,-6.35; 48 11.9,-5.08; 49 11.9,-3.81; 50 11.9,-2.54; 51 11.9,-1.27; 52 11.9,0; 53 11.9,1.27; 54 11.9,2.54; 55 11.9,3.81; 56 11.9,5.08; 57 11.9,6.35; 58 11.9,7.62; 59 11.9,8.89; 60 11.9,10.16

## Footprint QFP80 (pad centres in mm)
Quad Flat Pack
smd 1.3 x 0.38: 1 -8.1,6.175; 2 -8.1,5.525; 3 -8.1,4.875; 4 -8.1,4.225; 5 -8.1,3.575; 6 -8.1,2.925; 7 -8.1,2.275; 8 -8.1,1.625; 9 -8.1,0.975; 10 -8.1,0.325; 11 -8.1,-0.325; 12 -8.1,-0.975; 13 -8.1,-1.625; 14 -8.1,-2.275; 15 -8.1,-2.925; 16 -8.1,-3.575; 17 -8.1,-4.225; 18 -8.1,-4.875; 19 -8.1,-5.525; 20 -8.1,-6.175; 41 8.1,-6.175; 42 8.1,-5.525; 43 8.1,-4.875; 44 8.1,-4.225; 45 8.1,-3.575; 46 8.1,-2.925; 47 8.1,-2.275; 48 8.1,-1.625; 49 8.1,-0.975; 50 8.1,-0.325; 51 8.1,0.325; 52 8.1,0.975; 53 8.1,1.625; 54 8.1,2.275; 55 8.1,2.925; 56 8.1,3.575; 57 8.1,4.225; 58 8.1,4.875; 59 8.1,5.525; 60 8.1,6.175
smd 0.38 x 1.3: 21 -6.175,-8.1; 22 -5.525,-8.1; 23 -4.875,-8.1; 24 -4.225,-8.1; 25 -3.575,-8.1; 26 -2.925,-8.1; 27 -2.275,-8.1; 28 -1.625,-8.1; 29 -0.975,-8.1; 30 -0.325,-8.1; 31 0.325,-8.1; 32 0.975,-8.1; 33 1.625,-8.1; 34 2.275,-8.1; 35 2.925,-8.1; 36 3.575,-8.1; 37 4.225,-8.1; 38 4.875,-8.1; 39 5.525,-8.1; 40 6.175,-8.1; 61 6.175,8.1; 62 5.525,8.1; 63 4.875,8.1; 64 4.225,8.1; 65 3.575,8.1; 66 2.925,8.1; 67 2.275,8.1; 68 1.625,8.1; 69 0.975,8.1; 70 0.325,8.1; 71 -0.325,8.1; 72 -0.975,8.1; 73 -1.625,8.1; 74 -2.275,8.1; 75 -2.925,8.1; 76 -3.575,8.1; 77 -4.225,8.1; 78 -4.875,8.1; 79 -5.525,8.1; 80 -6.175,8.1

## Footprint S68 (pad centres in mm)
PLCC SOCKET
drill 0.813 round: 1 0,12.7
drill 0.813 octagon: 2 0,10.16; 3 -2.54,12.7; 4 -2.54,10.16; 5 -5.08,12.7; 6 -5.08,10.16; 7 -7.62,12.7; 8 -7.62,10.16; 9 -10.16,12.7; 10 -12.7,10.16; 11 -10.16,10.16; 12 -12.7,7.62; 13 -10.16,7.62; 14 -12.7,5.08; 15 -10.16,5.08; 16 -12.7,2.54; 17 -10.16,2.54; 18 -12.7,0; 19 -10.16,0; 20 -12.7,-2.54; 21 -10.16,-2.54; 22 -12.7,-5.08; 23 -10.16,-5.08; 24 -12.7,-7.62; 25 -10.16,-7.62; 26 -12.7,-10.16; 27 -10.16,-12.7; 28 -10.16,-10.16; 29 -7.62,-12.7; 30 -7.62,-10.16; 31 -5.08,-12.7; 32 -5.08,-10.16; 33 -2.54,-12.7; 34 -2.54,-10.16; 35 0,-12.7; 36 0,-10.16; 37 2.54,-12.7; 38 2.54,-10.16; 39 5.08,-12.7; 40 5.08,-10.16; 41 7.62,-12.7; 42 7.62,-10.16; 43 10.16,-12.7; 44 12.7,-10.16; 45 10.16,-10.16; 46 12.7,-7.62; 47 10.16,-7.62; 48 12.7,-5.08; 49 10.16,-5.08; 50 12.7,-2.54; 51 10.16,-2.54; 52 12.7,0; 53 10.16,0; 54 12.7,2.54; 55 10.16,2.54; 56 12.7,5.08; 57 10.16,5.08; 58 12.7,7.62; 59 10.16,7.62; 60 12.7,10.16; 61 10.16,12.7; 62 10.16,10.16; 63 7.62,12.7; 64 7.62,10.16; 65 5.08,12.7; 66 5.08,10.16; 67 2.54,12.7; 68 2.54,10.16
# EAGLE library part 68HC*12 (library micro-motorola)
Microcontroller with CAN-Bus, ADC

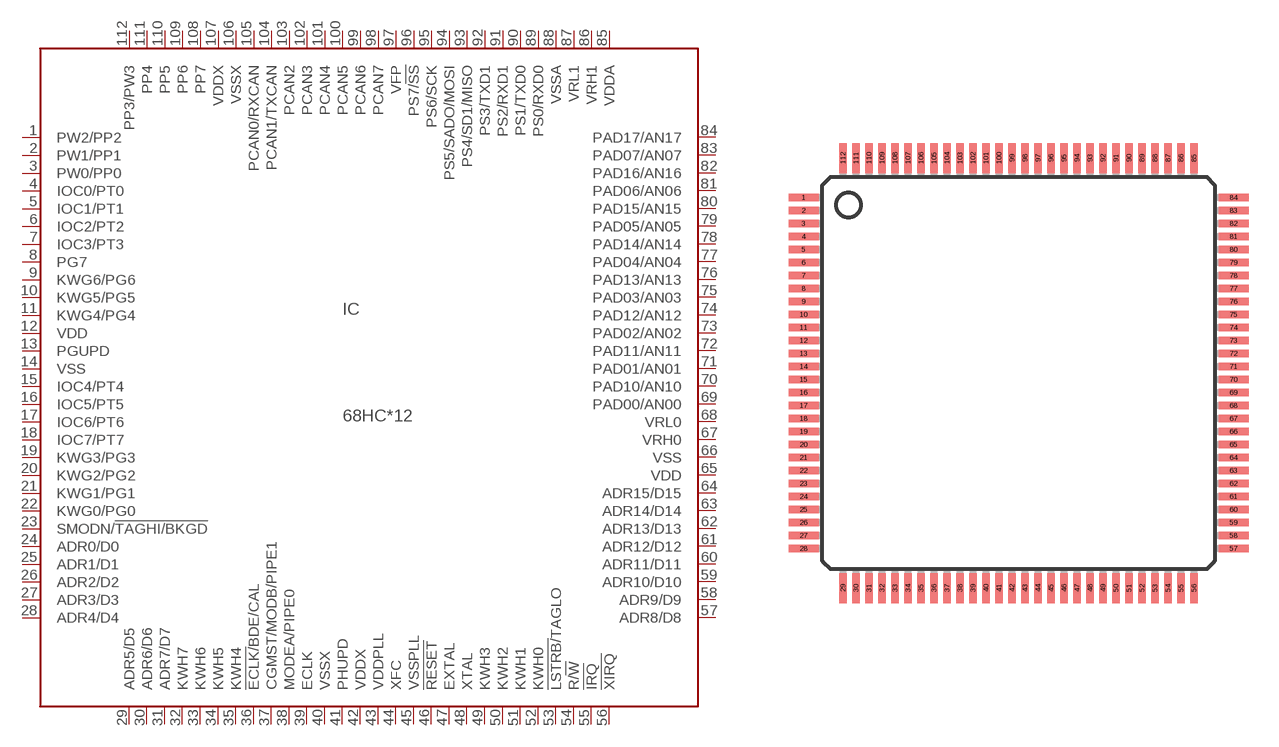
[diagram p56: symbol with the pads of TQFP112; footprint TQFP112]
Designator prefix IC

## 68HC912D60 (OC_FARNELL: unknown; OC_NEWARK: unknown)  [TQFP112]
1  PW2/PP2
2  PW1/PP1
3  PW0/PP0
4  IOC0/PT0
5  IOC1/PT1
6  IOC2/PT2
7  IOC3/PT3
8  PG7
9  KWG6/PG6
10  KWG5/PG5
11  KWG4/PG4
12  VDD  pwr
13  PGUPD  in
14  VSS  pwr
15  IOC4/PT4
16  IOC5/PT5
17  IOC6/PT6
18  IOC7/PT7
19  KWG3/PG3
20  KWG2/PG2
21  KWG1/PG1
22  KWG0/PG0
23  SMODN/!TAGHI/BKGD
24  ADR0/D0
25  ADR1/D1
26  ADR2/D2
27  ADR3/D3
28  ADR4/D4
29  ADR5/D5
30  ADR6/D6
31  ADR7/D7
32  KWH7
33  KWH6
34  KWH5
35  KWH4
36  !ECLK/!BDE/CAL
37  CGMST/MODB/PIPE1
38  MODEA/PIPE0
39  ECLK
40  VSSX  pwr
41  PHUPD  in
42  VDDX  pwr
43  VDDPLL  pwr
44  XFC  in
45  VSSPLL  pwr
46  !RESET
47  EXTAL  out
48  XTAL
49  KWH3
50  KWH2
51  KWH1
52  KWH0
53  !LSTRB/!TAGLO
54  R/!W
55  !IRQ  in
56  !XIRQ  in
57  ADR8/D8
58  ADR9/D9
59  ADR10/D10
60  ADR11/D11
61  ADR12/D12
62  ADR13/D13
63  ADR14/D14
64  ADR15/D15
65  VDD  pwr
66  VSS  pwr
67  VRH0  pwr
68  VRL0  pwr
69  PAD00/AN00  in
70  PAD10/AN10  in
71  PAD01/AN01  in
72  PAD11/AN11  in
73  PAD02/AN02  in
74  PAD12/AN12  in
75  PAD03/AN03  in
76  PAD13/AN13  in
77  PAD04/AN04  in
78  PAD14/AN14  in
79  PAD05/AN05  in
80  PAD15/AN15  in
81  PAD06/AN06  in
82  PAD16/AN16  in
83  PAD07/AN07  in
84  PAD17/AN17  in
85  VDDA  pwr
86  VRH1  pwr
87  VRL1  pwr
88  VSSA  pwr
89  PS0/RXD0
90  PS1/TXD0
91  PS2/RXD1
92  PS3/TXD1
93  PS4/SD1/MISO
94  PS5/SADO/MOSI
95  PS6/SCK
96  PS7/!SS
97  VFP  in
98  PCAN7
99  PCAN6
100  PCAN5
101  PCAN4
102  PCAN3
103  PCAN2
104  PCAN1/TXCAN  out
105  PCAN0/RXCAN  in
106  VSSX  pwr
107  VDDX  pwr
108  PP7
109  PP6
110  PP5
111  PP4
112  PP3/PW3

## Footprint TQFP112 (pad centres in mm)
Thin Quad Flat Pack 112-Pin LQFP (Case no. 987) 9S12A256DGV1.pdf
smd 1.5 x 0.37: 1 -10.75,8.775; 2 -10.75,8.125; 3 -10.75,7.475; 4 -10.75,6.825; 5 -10.75,6.175; 6 -10.75,5.525; 7 -10.75,4.875; 8 -10.75,4.225; 9 -10.75,3.575; 10 -10.75,2.925; 11 -10.75,2.275; 12 -10.75,1.625; 13 -10.75,0.975; 14 -10.75,0.325; 15 -10.75,-0.325; 16 -10.75,-0.975; 17 -10.75,-1.625; 18 -10.75,-2.275; 19 -10.75,-2.925; 20 -10.75,-3.575; 21 -10.75,-4.225; 22 -10.75,-4.875; 23 -10.75,-5.525; 24 -10.75,-6.175; 25 -10.75,-6.825; 26 -10.75,-7.475; 27 -10.75,-8.125; 28 -10.75,-8.775; 57 10.75,-8.775; 58 10.75,-8.125; 59 10.75,-7.475; 60 10.75,-6.825; 61 10.75,-6.175; 62 10.75,-5.525; 63 10.75,-4.875; 64 10.75,-4.225; 65 10.75,-3.575; 66 10.75,-2.925; 67 10.75,-2.275; 68 10.75,-1.625; 69 10.75,-0.975; 70 10.75,-0.325; 71 10.75,0.325; 72 10.75,0.975; 73 10.75,1.625; 74 10.75,2.275; 75 10.75,2.925; 76 10.75,3.575; 77 10.75,4.225; 78 10.75,4.875; 79 10.75,5.525; 80 10.75,6.175; 81 10.75,6.825; 82 10.75,7.475; 83 10.75,8.125; 84 10.75,8.775
smd 0.37 x 1.5: 29 -8.775,-10.75; 30 -8.125,-10.75; 31 -7.475,-10.75; 32 -6.825,-10.75; 33 -6.175,-10.75; 34 -5.525,-10.75; 35 -4.875,-10.75; 36 -4.225,-10.75; 37 -3.575,-10.75; 38 -2.925,-10.75; 39 -2.275,-10.75; 40 -1.625,-10.75; 41 -0.975,-10.75; 42 -0.325,-10.75; 43 0.325,-10.75; 44 0.975,-10.75; 45 1.625,-10.75; 46 2.275,-10.75; 47 2.925,-10.75; 48 3.575,-10.75; 49 4.225,-10.75; 50 4.875,-10.75; 51 5.525,-10.75; 52 6.175,-10.75; 53 6.825,-10.75; 54 7.475,-10.75; 55 8.125,-10.75; 56 8.775,-10.75; 85 8.775,10.75; 86 8.125,10.75; 87 7.475,10.75; 88 6.825,10.75; 89 6.175,10.75; 90 5.525,10.75; 91 4.875,10.75; 92 4.225,10.75; 93 3.575,10.75; 94 2.925,10.75; 95 2.275,10.75; 96 1.625,10.75; 97 0.975,10.75; 98 0.325,10.75; 99 -0.325,10.75; 100 -0.975,10.75; 101 -1.625,10.75; 102 -2.275,10.75; 103 -2.925,10.75; 104 -3.575,10.75; 105 -4.225,10.75; 106 -4.875,10.75; 107 -5.525,10.75; 108 -6.175,10.75; 109 -6.825,10.75; 110 -7.475,10.75; 111 -8.125,10.75; 112 -8.775,10.75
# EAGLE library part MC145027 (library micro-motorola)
DECODER SC41343

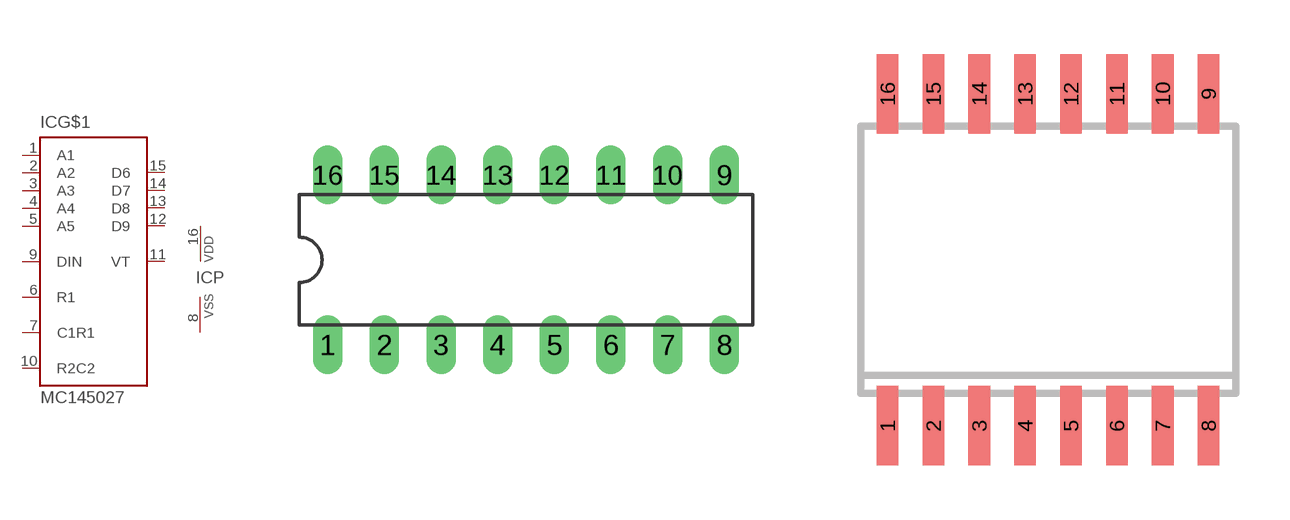
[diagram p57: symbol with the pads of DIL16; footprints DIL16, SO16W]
Designator prefix IC; gates G$1=MC145027 P=VSSVDD

## MC145027P (OC_FARNELL: unknown; OC_NEWARK: unknown)  [DIL16]
1  G$1:A1  in
2  G$1:A2  in
3  G$1:A3  in
4  G$1:A4  in
5  G$1:A5  in
6  G$1:R1  pas
7  G$1:C1R1  pas
8  P:VSS  pwr
9  G$1:DIN  in
10  G$1:R2C2  pas
11  G$1:VT  out
12  G$1:D9  out
13  G$1:D8  out
14  G$1:D7  out
15  G$1:D6  out
16  P:VDD  pwr

## MC145027DW (OC_FARNELL: unknown; OC_NEWARK: unknown)  [SO16W]
Pads as for DIL16

## Footprint DIL16 (pad centres in mm)
Dual In Line Package
drill 0.813 long: 1 -8.89,-3.81; 2 -6.35,-3.81; 3 -3.81,-3.81; 4 -1.27,-3.81; 5 1.27,-3.81; 6 3.81,-3.81; 7 6.35,-3.81; 8 8.89,-3.81; 9 8.89,3.81; 10 6.35,3.81; 11 3.81,3.81; 12 1.27,3.81; 13 -1.27,3.81; 14 -3.81,3.81; 15 -6.35,3.81; 16 -8.89,3.81

## Footprint SO16W (pad centres in mm)
SMALL OUTLINE INTEGRATED CIRCUIT wide body 7.5 mm/JEDEC MS-013AA
smd 0.6 x 2.2: 1 -4.445,-4.6; 2 -3.175,-4.6; 3 -1.905,-4.6; 4 -0.635,-4.6; 5 0.635,-4.6; 6 1.905,-4.6; 7 3.175,-4.6; 8 4.445,-4.6; 9 4.445,4.6; 10 3.175,4.6; 11 1.905,4.6; 12 0.635,4.6; 13 -0.635,4.6; 14 -1.905,4.6; 15 -3.175,4.6; 16 -4.445,4.6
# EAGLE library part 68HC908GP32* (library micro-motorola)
MC68HC908GP32 MC68HC08GP32 Source: www.motorola.com .. MC68HC908GP32.pdf

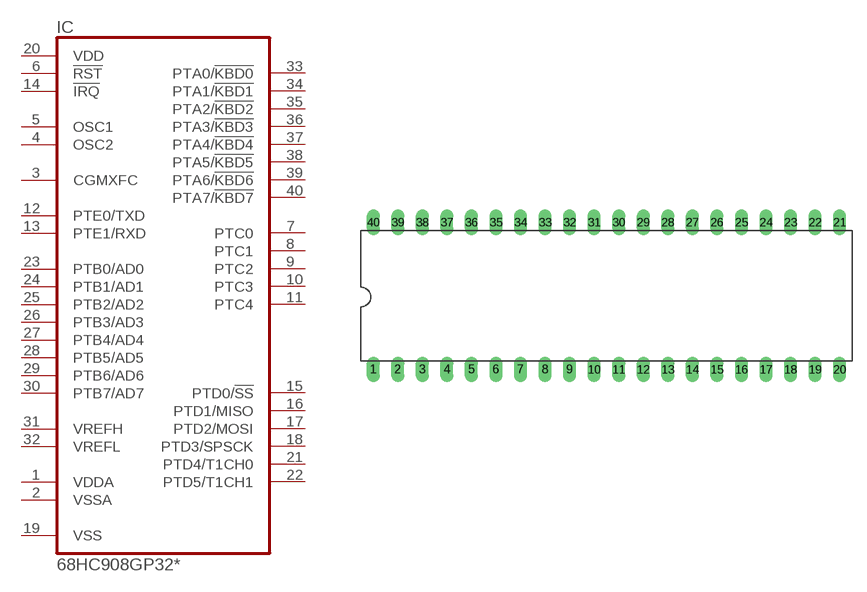
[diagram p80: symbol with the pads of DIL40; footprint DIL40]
Designator prefix IC

## 68HC908GP32 (MF: MOTOROLA; MPN: MC68HC908GP32CP; OC_FARNELL: 1200519; OC_NEWARK: 95B4407)  [DIL40]
1  VDDA  pwr
2  VSSA  pwr
3  CGMXFC  in
4  OSC2  in
5  OSC1  in
6  !RST  in
7  PTC0
8  PTC1
9  PTC2
10  PTC3
11  PTC4
12  PTE0/TXD
13  PTE1/RXD
14  !IRQ  in
15  PTD0/!SS
16  PTD1/MISO
17  PTD2/MOSI
18  PTD3/SPSCK
19  VSS  pwr
20  VDD  pwr
21  PTD4/T1CH0
22  PTD5/T1CH1
23  PTB0/AD0
24  PTB1/AD1
25  PTB2/AD2
26  PTB3/AD3
27  PTB4/AD4
28  PTB5/AD5
29  PTB6/AD6
30  PTB7/AD7
31  VREFH  in
32  VREFL  in
33  PTA0/!KBD0
34  PTA1/!KBD1
35  PTA2/!KBD2
36  PTA3/!KBD3
37  PTA4/!KBD4
38  PTA5/!KBD5
39  PTA6/!KBD6
40  PTA7/!KBD7

## Footprint DIL40 (pad centres in mm)
Dual In Line Package
drill 0.813 long: 1 -24.13,-7.62; 2 -21.59,-7.62; 3 -19.05,-7.62; 4 -16.51,-7.62; 5 -13.97,-7.62; 6 -11.43,-7.62; 7 -8.89,-7.62; 8 -6.35,-7.62; 9 -3.81,-7.62; 10 -1.27,-7.62; 11 1.27,-7.62; 12 3.81,-7.62; 13 6.35,-7.62; 14 8.89,-7.62; 15 11.43,-7.62; 16 13.97,-7.62; 17 16.51,-7.62; 18 19.05,-7.62; 19 21.59,-7.62; 20 24.13,-7.62; 21 24.13,7.62; 22 21.59,7.62; 23 19.05,7.62; 24 16.51,7.62; 25 13.97,7.62; 26 11.43,7.62; 27 8.89,7.62; 28 6.35,7.62; 29 3.81,7.62; 30 1.27,7.62; 31 -1.27,7.62; 32 -3.81,7.62; 33 -6.35,7.62; 34 -8.89,7.62; 35 -11.43,7.62; 36 -13.97,7.62; 37 -16.51,7.62; 38 -19.05,7.62; 39 -21.59,7.62; 40 -24.13,7.62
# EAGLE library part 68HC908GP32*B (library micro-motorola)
MC68HC908GP32 MC68HC08GP32 Source: www.motorola.com .. MC68HC908GP32.pdf

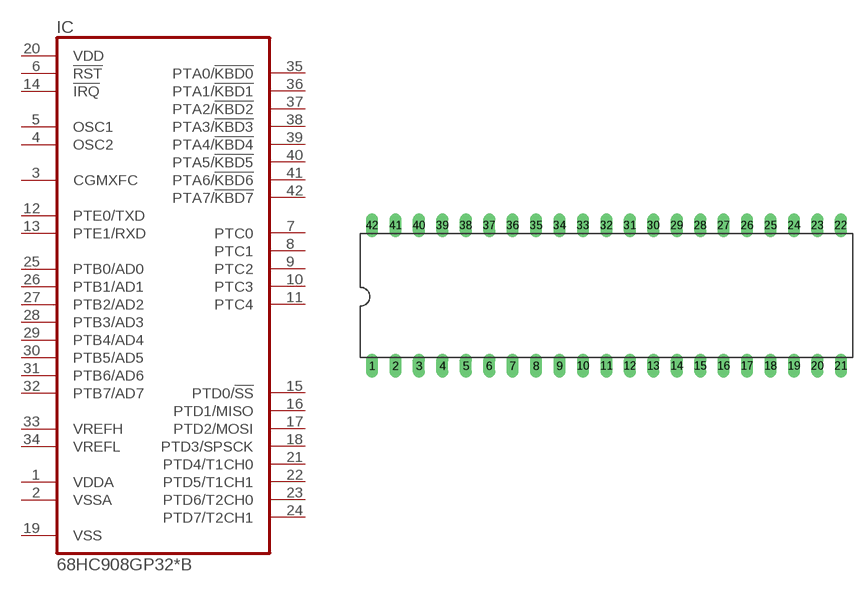
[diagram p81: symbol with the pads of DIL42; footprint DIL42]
Designator prefix IC

## 68HC908GP32CB (MF: MOTOROLA; MPN: MC68HC908GP32CB; OC_FARNELL: 1200520; OC_NEWARK: 75C2312), 68HC908GP32MB (MF: MOTOROLA; MPN: MC68HC908GP32CB; OC_FARNELL: unknown; OC_NEWARK: 75C2312), 68HC908GP32VB (MF: MOTOROLA; MPN: MC68HC908GP32CB; OC_FARNELL: unknown; OC_NEWARK: 75C2312)  [DIL42]
1  VDDA  pwr
2  VSSA  pwr
3  CGMXFC  in
4  OSC2  in
5  OSC1  in
6  !RST  in
7  PTC0
8  PTC1
9  PTC2
10  PTC3
11  PTC4
12  PTE0/TXD
13  PTE1/RXD
14  !IRQ  in
15  PTD0/!SS
16  PTD1/MISO
17  PTD2/MOSI
18  PTD3/SPSCK
19  VSS  pwr
20  VDD  pwr
21  PTD4/T1CH0
22  PTD5/T1CH1
23  PTD6/T2CH0
24  PTD7/T2CH1
25  PTB0/AD0
26  PTB1/AD1
27  PTB2/AD2
28  PTB3/AD3
29  PTB4/AD4
30  PTB5/AD5
31  PTB6/AD6
32  PTB7/AD7
33  VREFH  in
34  VREFL  in
35  PTA0/!KBD0
36  PTA1/!KBD1
37  PTA2/!KBD2
38  PTA3/!KBD3
39  PTA4/!KBD4
40  PTA5/!KBD5
41  PTA6/!KBD6
42  PTA7/!KBD7

## Footprint DIL42 (pad centres in mm)
Dual In Line Package
drill 0.813 long: 1 -25.4,-7.62; 2 -22.86,-7.62; 3 -20.32,-7.62; 4 -17.78,-7.62; 5 -15.24,-7.62; 6 -12.7,-7.62; 7 -10.16,-7.62; 8 -7.62,-7.62; 9 -5.08,-7.62; 10 -2.54,-7.62; 11 0,-7.62; 12 2.54,-7.62; 13 5.08,-7.62; 14 7.62,-7.62; 15 10.16,-7.62; 16 12.7,-7.62; 17 15.24,-7.62; 18 17.78,-7.62; 19 20.32,-7.62; 20 22.86,-7.62; 21 25.4,-7.62; 22 25.4,7.62; 23 22.86,7.62; 24 20.32,7.62; 25 17.78,7.62; 26 15.24,7.62; 27 12.7,7.62; 28 10.16,7.62; 29 7.62,7.62; 30 5.08,7.62; 31 2.54,7.62; 32 0,7.62; 33 -2.54,7.62; 34 -5.08,7.62; 35 -7.62,7.62; 36 -10.16,7.62; 37 -12.7,7.62; 38 -15.24,7.62; 39 -17.78,7.62; 40 -20.32,7.62; 41 -22.86,7.62; 42 -25.4,7.62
